VERSION 5.7 ;
  NOWIREEXTENSIONATPIN ON ;
  DIVIDERCHAR "/" ;
  BUSBITCHARS "[]" ;
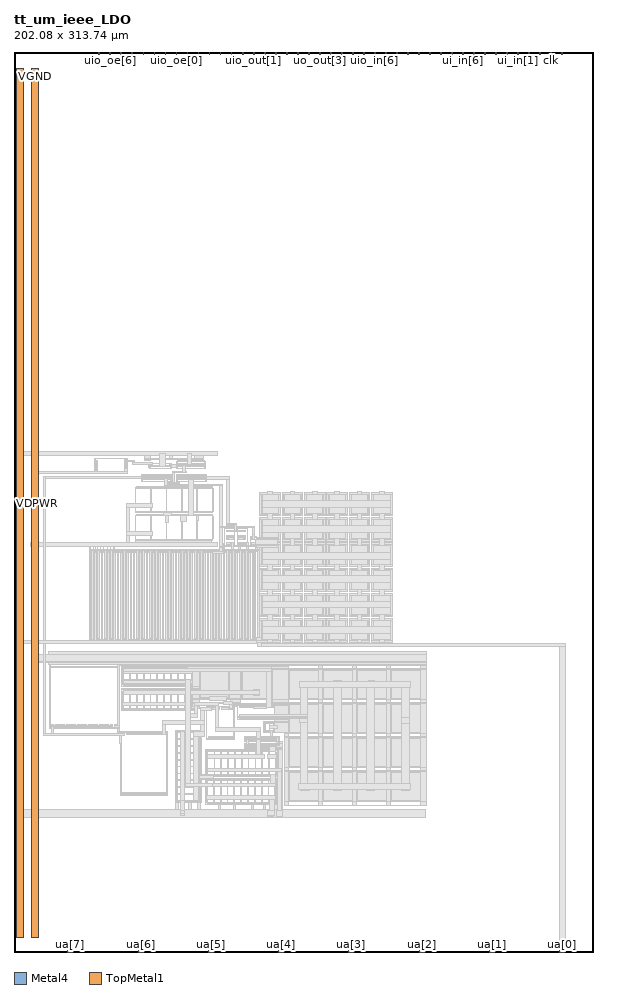
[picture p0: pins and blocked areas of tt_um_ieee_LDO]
MACRO tt_um_ieee_LDO
  CLASS BLOCK ;
  FOREIGN tt_um_ieee_LDO ;
  ORIGIN 0.000 0.000 ;
  SIZE 202.080 BY 313.740 ;
  PIN clk
    PORT
      LAYER Metal4 ;
        RECT 187.050 312.740 187.350 313.740 ;
    END
  END clk
  PIN ena
    PORT
      LAYER Metal4 ;
        RECT 190.890 312.740 191.190 313.740 ;
    END
  END ena
  PIN rst_n
    PORT
      LAYER Metal4 ;
        RECT 183.210 312.740 183.510 313.740 ;
    END
  END rst_n
  PIN ua[0]
    ANTENNADIFFAREA 559.200012 ;
    PORT
      LAYER TopMetal1 ;
        RECT 190.165 0.000 191.915 2.000 ;
    END
  END ua[0]
  PIN ua[1]
    PORT
      LAYER TopMetal1 ;
        RECT 165.685 0.000 167.435 2.000 ;
    END
  END ua[1]
  PIN ua[2]
    PORT
      LAYER TopMetal1 ;
        RECT 141.205 0.000 142.955 2.000 ;
    END
  END ua[2]
  PIN ua[3]
    PORT
      LAYER TopMetal1 ;
        RECT 116.725 0.000 118.475 2.000 ;
    END
  END ua[3]
  PIN ua[4]
    PORT
      LAYER TopMetal1 ;
        RECT 92.245 0.000 93.995 2.000 ;
    END
  END ua[4]
  PIN ua[5]
    PORT
      LAYER TopMetal1 ;
        RECT 67.765 0.000 69.515 2.000 ;
    END
  END ua[5]
  PIN ua[6]
    PORT
      LAYER TopMetal1 ;
        RECT 43.285 0.000 45.035 2.000 ;
    END
  END ua[6]
  PIN ua[7]
    PORT
      LAYER TopMetal1 ;
        RECT 18.805 0.000 20.555 2.000 ;
    END
  END ua[7]
  PIN ui_in[0]
    PORT
      LAYER Metal4 ;
        RECT 179.370 312.740 179.670 313.740 ;
    END
  END ui_in[0]
  PIN ui_in[1]
    PORT
      LAYER Metal4 ;
        RECT 175.530 312.740 175.830 313.740 ;
    END
  END ui_in[1]
  PIN ui_in[2]
    PORT
      LAYER Metal4 ;
        RECT 171.690 312.740 171.990 313.740 ;
    END
  END ui_in[2]
  PIN ui_in[3]
    PORT
      LAYER Metal4 ;
        RECT 167.850 312.740 168.150 313.740 ;
    END
  END ui_in[3]
  PIN ui_in[4]
    PORT
      LAYER Metal4 ;
        RECT 164.010 312.740 164.310 313.740 ;
    END
  END ui_in[4]
  PIN ui_in[5]
    PORT
      LAYER Metal4 ;
        RECT 160.170 312.740 160.470 313.740 ;
    END
  END ui_in[5]
  PIN ui_in[6]
    PORT
      LAYER Metal4 ;
        RECT 156.330 312.740 156.630 313.740 ;
    END
  END ui_in[6]
  PIN ui_in[7]
    PORT
      LAYER Metal4 ;
        RECT 152.490 312.740 152.790 313.740 ;
    END
  END ui_in[7]
  PIN uio_in[0]
    PORT
      LAYER Metal4 ;
        RECT 148.650 312.740 148.950 313.740 ;
    END
  END uio_in[0]
  PIN uio_in[1]
    PORT
      LAYER Metal4 ;
        RECT 144.810 312.740 145.110 313.740 ;
    END
  END uio_in[1]
  PIN uio_in[2]
    PORT
      LAYER Metal4 ;
        RECT 140.970 312.740 141.270 313.740 ;
    END
  END uio_in[2]
  PIN uio_in[3]
    PORT
      LAYER Metal4 ;
        RECT 137.130 312.740 137.430 313.740 ;
    END
  END uio_in[3]
  PIN uio_in[4]
    PORT
      LAYER Metal4 ;
        RECT 133.290 312.740 133.590 313.740 ;
    END
  END uio_in[4]
  PIN uio_in[5]
    PORT
      LAYER Metal4 ;
        RECT 129.450 312.740 129.750 313.740 ;
    END
  END uio_in[5]
  PIN uio_in[6]
    PORT
      LAYER Metal4 ;
        RECT 125.610 312.740 125.910 313.740 ;
    END
  END uio_in[6]
  PIN uio_in[7]
    PORT
      LAYER Metal4 ;
        RECT 121.770 312.740 122.070 313.740 ;
    END
  END uio_in[7]
  PIN uio_oe[0]
    PORT
      LAYER Metal4 ;
        RECT 56.490 312.740 56.790 313.740 ;
    END
  END uio_oe[0]
  PIN uio_oe[1]
    PORT
      LAYER Metal4 ;
        RECT 52.650 312.740 52.950 313.740 ;
    END
  END uio_oe[1]
  PIN uio_oe[2]
    PORT
      LAYER Metal4 ;
        RECT 48.810 312.740 49.110 313.740 ;
    END
  END uio_oe[2]
  PIN uio_oe[3]
    PORT
      LAYER Metal4 ;
        RECT 44.970 312.740 45.270 313.740 ;
    END
  END uio_oe[3]
  PIN uio_oe[4]
    PORT
      LAYER Metal4 ;
        RECT 41.130 312.740 41.430 313.740 ;
    END
  END uio_oe[4]
  PIN uio_oe[5]
    PORT
      LAYER Metal4 ;
        RECT 37.290 312.740 37.590 313.740 ;
    END
  END uio_oe[5]
  PIN uio_oe[6]
    PORT
      LAYER Metal4 ;
        RECT 33.450 312.740 33.750 313.740 ;
    END
  END uio_oe[6]
  PIN uio_oe[7]
    PORT
      LAYER Metal4 ;
        RECT 29.610 312.740 29.910 313.740 ;
    END
  END uio_oe[7]
  PIN uio_out[0]
    PORT
      LAYER Metal4 ;
        RECT 87.210 312.740 87.510 313.740 ;
    END
  END uio_out[0]
  PIN uio_out[1]
    PORT
      LAYER Metal4 ;
        RECT 83.370 312.740 83.670 313.740 ;
    END
  END uio_out[1]
  PIN uio_out[2]
    PORT
      LAYER Metal4 ;
        RECT 79.530 312.740 79.830 313.740 ;
    END
  END uio_out[2]
  PIN uio_out[3]
    PORT
      LAYER Metal4 ;
        RECT 75.690 312.740 75.990 313.740 ;
    END
  END uio_out[3]
  PIN uio_out[4]
    PORT
      LAYER Metal4 ;
        RECT 71.850 312.740 72.150 313.740 ;
    END
  END uio_out[4]
  PIN uio_out[5]
    PORT
      LAYER Metal4 ;
        RECT 68.010 312.740 68.310 313.740 ;
    END
  END uio_out[5]
  PIN uio_out[6]
    PORT
      LAYER Metal4 ;
        RECT 64.170 312.740 64.470 313.740 ;
    END
  END uio_out[6]
  PIN uio_out[7]
    PORT
      LAYER Metal4 ;
        RECT 60.330 312.740 60.630 313.740 ;
    END
  END uio_out[7]
  PIN uo_out[0]
    PORT
      LAYER Metal4 ;
        RECT 117.930 312.740 118.230 313.740 ;
    END
  END uo_out[0]
  PIN uo_out[1]
    PORT
      LAYER Metal4 ;
        RECT 114.090 312.740 114.390 313.740 ;
    END
  END uo_out[1]
  PIN uo_out[2]
    PORT
      LAYER Metal4 ;
        RECT 110.250 312.740 110.550 313.740 ;
    END
  END uo_out[2]
  PIN uo_out[3]
    PORT
      LAYER Metal4 ;
        RECT 106.410 312.740 106.710 313.740 ;
    END
  END uo_out[3]
  PIN uo_out[4]
    PORT
      LAYER Metal4 ;
        RECT 102.570 312.740 102.870 313.740 ;
    END
  END uo_out[4]
  PIN uo_out[5]
    PORT
      LAYER Metal4 ;
        RECT 98.730 312.740 99.030 313.740 ;
    END
  END uo_out[5]
  PIN uo_out[6]
    PORT
      LAYER Metal4 ;
        RECT 94.890 312.740 95.190 313.740 ;
    END
  END uo_out[6]
  PIN uo_out[7]
    PORT
      LAYER Metal4 ;
        RECT 91.050 312.740 91.350 313.740 ;
    END
  END uo_out[7]
  PIN VDPWR
    USE POWER ;
    PORT
      LAYER TopMetal1 ;
        RECT 1.000 5.000 3.400 308.000 ;
    END
  END VDPWR
  PIN VGND
    USE GROUND ;
    PORT
      LAYER TopMetal1 ;
        RECT 6.000 5.000 8.400 308.000 ;
    END
  END VGND
  OBS
      LAYER GatPoly ;
        RECT 28.760 170.900 29.190 171.400 ;
        RECT 38.390 170.900 38.820 171.400 ;
        RECT 56.500 170.430 56.870 170.910 ;
        RECT 66.540 170.430 66.910 170.910 ;
        RECT 28.760 169.920 29.190 170.420 ;
        RECT 38.390 169.920 38.820 170.420 ;
        RECT 47.060 169.630 47.430 170.110 ;
        RECT 54.680 169.630 55.050 170.110 ;
        RECT 56.500 169.570 56.870 170.050 ;
        RECT 66.540 169.570 66.910 170.050 ;
        RECT 28.760 168.940 29.190 169.440 ;
        RECT 38.390 168.940 38.820 169.440 ;
        RECT 47.060 168.770 47.430 169.250 ;
        RECT 54.680 168.770 55.050 169.250 ;
        RECT 56.500 168.710 56.870 169.190 ;
        RECT 66.540 168.710 66.910 169.190 ;
        RECT 28.760 167.960 29.190 168.460 ;
        RECT 38.390 167.960 38.820 168.460 ;
        RECT 44.290 165.770 44.660 166.170 ;
        RECT 54.660 165.770 55.030 166.170 ;
        RECT 56.500 165.730 56.870 166.130 ;
        RECT 66.870 165.730 67.240 166.130 ;
        RECT 44.290 164.990 44.660 165.390 ;
        RECT 54.660 164.990 55.030 165.390 ;
        RECT 56.500 164.950 56.870 165.350 ;
        RECT 66.870 164.950 67.240 165.350 ;
        RECT 44.290 164.210 44.660 164.610 ;
        RECT 54.660 164.210 55.030 164.610 ;
        RECT 56.500 164.170 56.870 164.570 ;
        RECT 66.870 164.170 67.240 164.570 ;
        RECT 42.570 161.740 47.570 162.110 ;
        RECT 47.950 161.740 52.950 162.110 ;
        RECT 53.330 161.740 58.330 162.110 ;
        RECT 58.710 161.740 63.710 162.110 ;
        RECT 64.090 161.740 69.090 162.110 ;
        RECT 42.570 153.270 47.570 153.640 ;
        RECT 47.950 153.270 52.950 153.640 ;
        RECT 53.330 153.270 58.330 153.640 ;
        RECT 58.710 153.270 63.710 153.640 ;
        RECT 64.090 153.270 69.090 153.640 ;
        RECT 42.570 152.020 47.570 152.390 ;
        RECT 47.950 152.020 52.950 152.390 ;
        RECT 53.330 152.020 58.330 152.390 ;
        RECT 58.710 152.020 63.710 152.390 ;
        RECT 64.090 152.020 69.090 152.390 ;
        RECT 73.930 146.595 74.430 147.025 ;
        RECT 74.910 146.595 75.410 147.025 ;
        RECT 75.890 146.595 76.390 147.025 ;
        RECT 78.390 146.575 78.890 147.005 ;
        RECT 79.370 146.575 79.870 147.005 ;
        RECT 80.350 146.575 80.850 147.005 ;
        RECT 73.930 144.865 74.430 145.295 ;
        RECT 74.910 144.865 75.410 145.295 ;
        RECT 75.890 144.865 76.390 145.295 ;
        RECT 78.390 144.845 78.890 145.275 ;
        RECT 79.370 144.845 79.870 145.275 ;
        RECT 80.350 144.845 80.850 145.275 ;
        RECT 42.570 143.550 47.570 143.920 ;
        RECT 47.950 143.550 52.950 143.920 ;
        RECT 53.330 143.550 58.330 143.920 ;
        RECT 58.710 143.550 63.710 143.920 ;
        RECT 64.090 143.550 69.090 143.920 ;
        RECT 73.930 143.915 74.430 144.345 ;
        RECT 74.910 143.915 75.410 144.345 ;
        RECT 75.890 143.915 76.390 144.345 ;
        RECT 78.390 143.895 78.890 144.325 ;
        RECT 79.370 143.895 79.870 144.325 ;
        RECT 80.350 143.895 80.850 144.325 ;
        RECT 82.930 143.625 83.930 144.055 ;
        RECT 73.930 142.185 74.430 142.615 ;
        RECT 74.910 142.185 75.410 142.615 ;
        RECT 75.890 142.185 76.390 142.615 ;
        RECT 78.390 142.165 78.890 142.595 ;
        RECT 79.370 142.165 79.870 142.595 ;
        RECT 80.350 142.165 80.850 142.595 ;
        RECT 82.930 142.195 83.930 142.625 ;
        RECT 27.670 139.095 28.070 139.465 ;
        RECT 28.790 139.095 29.190 139.465 ;
        RECT 29.910 139.095 30.310 139.465 ;
        RECT 31.030 139.095 31.430 139.465 ;
        RECT 32.150 139.095 32.550 139.465 ;
        RECT 33.270 139.095 33.670 139.465 ;
        RECT 34.390 139.095 34.790 139.465 ;
        RECT 35.510 139.095 35.910 139.465 ;
        RECT 36.630 139.095 37.030 139.465 ;
        RECT 37.750 139.095 38.150 139.465 ;
        RECT 38.870 139.095 39.270 139.465 ;
        RECT 39.990 139.095 40.390 139.465 ;
        RECT 41.110 139.095 41.510 139.465 ;
        RECT 42.230 139.095 42.630 139.465 ;
        RECT 43.350 139.095 43.750 139.465 ;
        RECT 44.470 139.095 44.870 139.465 ;
        RECT 45.590 139.095 45.990 139.465 ;
        RECT 46.710 139.095 47.110 139.465 ;
        RECT 47.830 139.095 48.230 139.465 ;
        RECT 48.950 139.095 49.350 139.465 ;
        RECT 50.070 139.095 50.470 139.465 ;
        RECT 51.190 139.095 51.590 139.465 ;
        RECT 52.310 139.095 52.710 139.465 ;
        RECT 53.430 139.095 53.830 139.465 ;
        RECT 54.550 139.095 54.950 139.465 ;
        RECT 55.670 139.095 56.070 139.465 ;
        RECT 56.790 139.095 57.190 139.465 ;
        RECT 57.910 139.095 58.310 139.465 ;
        RECT 59.030 139.095 59.430 139.465 ;
        RECT 60.150 139.095 60.550 139.465 ;
        RECT 61.270 139.095 61.670 139.465 ;
        RECT 62.390 139.095 62.790 139.465 ;
        RECT 63.510 139.095 63.910 139.465 ;
        RECT 64.630 139.095 65.030 139.465 ;
        RECT 65.750 139.095 66.150 139.465 ;
        RECT 66.870 139.095 67.270 139.465 ;
        RECT 67.990 139.095 68.390 139.465 ;
        RECT 69.110 139.095 69.510 139.465 ;
        RECT 70.230 139.095 70.630 139.465 ;
        RECT 71.350 139.095 71.750 139.465 ;
        RECT 72.470 139.095 72.870 139.465 ;
        RECT 73.590 139.095 73.990 139.465 ;
        RECT 74.710 139.095 75.110 139.465 ;
        RECT 75.830 139.095 76.230 139.465 ;
        RECT 76.950 139.095 77.350 139.465 ;
        RECT 78.070 139.095 78.470 139.465 ;
        RECT 79.190 139.095 79.590 139.465 ;
        RECT 80.310 139.095 80.710 139.465 ;
        RECT 81.430 139.095 81.830 139.465 ;
        RECT 82.550 139.095 82.950 139.465 ;
        RECT 27.670 108.725 28.070 109.095 ;
        RECT 28.790 108.725 29.190 109.095 ;
        RECT 29.910 108.725 30.310 109.095 ;
        RECT 31.030 108.725 31.430 109.095 ;
        RECT 32.150 108.725 32.550 109.095 ;
        RECT 33.270 108.725 33.670 109.095 ;
        RECT 34.390 108.725 34.790 109.095 ;
        RECT 35.510 108.725 35.910 109.095 ;
        RECT 36.630 108.725 37.030 109.095 ;
        RECT 37.750 108.725 38.150 109.095 ;
        RECT 38.870 108.725 39.270 109.095 ;
        RECT 39.990 108.725 40.390 109.095 ;
        RECT 41.110 108.725 41.510 109.095 ;
        RECT 42.230 108.725 42.630 109.095 ;
        RECT 43.350 108.725 43.750 109.095 ;
        RECT 44.470 108.725 44.870 109.095 ;
        RECT 45.590 108.725 45.990 109.095 ;
        RECT 46.710 108.725 47.110 109.095 ;
        RECT 47.830 108.725 48.230 109.095 ;
        RECT 48.950 108.725 49.350 109.095 ;
        RECT 50.070 108.725 50.470 109.095 ;
        RECT 51.190 108.725 51.590 109.095 ;
        RECT 52.310 108.725 52.710 109.095 ;
        RECT 53.430 108.725 53.830 109.095 ;
        RECT 54.550 108.725 54.950 109.095 ;
        RECT 55.670 108.725 56.070 109.095 ;
        RECT 56.790 108.725 57.190 109.095 ;
        RECT 57.910 108.725 58.310 109.095 ;
        RECT 59.030 108.725 59.430 109.095 ;
        RECT 60.150 108.725 60.550 109.095 ;
        RECT 61.270 108.725 61.670 109.095 ;
        RECT 62.390 108.725 62.790 109.095 ;
        RECT 63.510 108.725 63.910 109.095 ;
        RECT 64.630 108.725 65.030 109.095 ;
        RECT 65.750 108.725 66.150 109.095 ;
        RECT 66.870 108.725 67.270 109.095 ;
        RECT 67.990 108.725 68.390 109.095 ;
        RECT 69.110 108.725 69.510 109.095 ;
        RECT 70.230 108.725 70.630 109.095 ;
        RECT 71.350 108.725 71.750 109.095 ;
        RECT 72.470 108.725 72.870 109.095 ;
        RECT 73.590 108.725 73.990 109.095 ;
        RECT 74.710 108.725 75.110 109.095 ;
        RECT 75.830 108.725 76.230 109.095 ;
        RECT 76.950 108.725 77.350 109.095 ;
        RECT 78.070 108.725 78.470 109.095 ;
        RECT 79.190 108.725 79.590 109.095 ;
        RECT 80.310 108.725 80.710 109.095 ;
        RECT 81.430 108.725 81.830 109.095 ;
        RECT 82.550 108.725 82.950 109.095 ;
        RECT 13.100 99.140 13.900 99.570 ;
        RECT 14.380 99.140 15.180 99.570 ;
        RECT 15.660 99.140 16.460 99.570 ;
        RECT 16.940 99.140 17.740 99.570 ;
        RECT 18.220 99.140 19.020 99.570 ;
        RECT 19.500 99.140 20.300 99.570 ;
        RECT 20.780 99.140 21.580 99.570 ;
        RECT 22.060 99.140 22.860 99.570 ;
        RECT 23.340 99.140 24.140 99.570 ;
        RECT 24.620 99.140 25.420 99.570 ;
        RECT 25.900 99.140 26.700 99.570 ;
        RECT 27.180 99.140 27.980 99.570 ;
        RECT 28.460 99.140 29.260 99.570 ;
        RECT 29.740 99.140 30.540 99.570 ;
        RECT 31.020 99.140 31.820 99.570 ;
        RECT 32.300 99.140 33.100 99.570 ;
        RECT 33.580 99.140 34.380 99.570 ;
        RECT 34.860 99.140 35.660 99.570 ;
        RECT 38.260 99.140 40.260 99.510 ;
        RECT 40.640 99.140 42.640 99.510 ;
        RECT 43.020 99.140 45.020 99.510 ;
        RECT 45.400 99.140 47.400 99.510 ;
        RECT 47.780 99.140 49.780 99.510 ;
        RECT 50.160 99.140 52.160 99.510 ;
        RECT 52.540 99.140 54.540 99.510 ;
        RECT 54.920 99.140 56.920 99.510 ;
        RECT 57.300 99.140 59.300 99.510 ;
        RECT 59.680 99.140 61.680 99.510 ;
        RECT 38.260 92.770 40.260 93.140 ;
        RECT 40.640 92.770 42.640 93.140 ;
        RECT 43.020 92.770 45.020 93.140 ;
        RECT 45.400 92.770 47.400 93.140 ;
        RECT 47.780 92.770 49.780 93.140 ;
        RECT 50.160 92.770 52.160 93.140 ;
        RECT 52.540 92.770 54.540 93.140 ;
        RECT 54.920 92.770 56.920 93.140 ;
        RECT 57.300 92.770 59.300 93.140 ;
        RECT 59.680 92.770 61.680 93.140 ;
        RECT 38.260 91.020 40.260 91.390 ;
        RECT 40.640 91.020 42.640 91.390 ;
        RECT 43.020 91.020 45.020 91.390 ;
        RECT 45.400 91.020 47.400 91.390 ;
        RECT 47.780 91.020 49.780 91.390 ;
        RECT 50.160 91.020 52.160 91.390 ;
        RECT 52.540 91.020 54.540 91.390 ;
        RECT 54.920 91.020 56.920 91.390 ;
        RECT 57.300 91.020 59.300 91.390 ;
        RECT 59.680 91.020 61.680 91.390 ;
        RECT 38.260 84.650 40.260 85.020 ;
        RECT 40.640 84.650 42.640 85.020 ;
        RECT 43.020 84.650 45.020 85.020 ;
        RECT 45.400 84.650 47.400 85.020 ;
        RECT 47.780 84.650 49.780 85.020 ;
        RECT 50.160 84.650 52.160 85.020 ;
        RECT 52.540 84.650 54.540 85.020 ;
        RECT 54.920 84.650 56.920 85.020 ;
        RECT 57.300 84.650 59.300 85.020 ;
        RECT 59.680 84.650 61.680 85.020 ;
        RECT 67.740 84.670 68.740 85.100 ;
        RECT 69.220 84.670 70.220 85.100 ;
        RECT 70.700 84.670 71.700 85.100 ;
        RECT 72.180 84.670 73.180 85.100 ;
        RECT 73.660 84.670 74.660 85.100 ;
        RECT 75.140 84.670 76.140 85.100 ;
        RECT 78.480 85.070 80.480 85.500 ;
        RECT 80.960 85.070 82.960 85.500 ;
        RECT 83.440 85.070 85.440 85.500 ;
        RECT 85.920 85.070 87.920 85.500 ;
        RECT 88.400 85.070 90.400 85.500 ;
        RECT 78.480 81.640 80.480 82.070 ;
        RECT 80.960 81.640 82.960 82.070 ;
        RECT 83.440 81.640 85.440 82.070 ;
        RECT 85.920 81.640 87.920 82.070 ;
        RECT 88.400 81.640 90.400 82.070 ;
        RECT 87.880 79.550 88.880 79.920 ;
        RECT 89.260 79.550 90.260 79.920 ;
        RECT 13.100 78.710 13.900 79.140 ;
        RECT 14.380 78.710 15.180 79.140 ;
        RECT 15.660 78.710 16.460 79.140 ;
        RECT 16.940 78.710 17.740 79.140 ;
        RECT 18.220 78.710 19.020 79.140 ;
        RECT 19.500 78.710 20.300 79.140 ;
        RECT 20.780 78.710 21.580 79.140 ;
        RECT 22.060 78.710 22.860 79.140 ;
        RECT 23.340 78.710 24.140 79.140 ;
        RECT 24.620 78.710 25.420 79.140 ;
        RECT 25.900 78.710 26.700 79.140 ;
        RECT 27.180 78.710 27.980 79.140 ;
        RECT 28.460 78.710 29.260 79.140 ;
        RECT 29.740 78.710 30.540 79.140 ;
        RECT 31.020 78.710 31.820 79.140 ;
        RECT 32.300 78.710 33.100 79.140 ;
        RECT 33.580 78.710 34.380 79.140 ;
        RECT 34.860 78.710 35.660 79.140 ;
        RECT 87.880 76.680 88.880 77.050 ;
        RECT 89.260 76.680 90.260 77.050 ;
        RECT 37.850 75.680 38.650 76.110 ;
        RECT 39.130 75.680 39.930 76.110 ;
        RECT 40.410 75.680 41.210 76.110 ;
        RECT 41.690 75.680 42.490 76.110 ;
        RECT 42.970 75.680 43.770 76.110 ;
        RECT 44.250 75.680 45.050 76.110 ;
        RECT 45.530 75.680 46.330 76.110 ;
        RECT 46.810 75.680 47.610 76.110 ;
        RECT 48.090 75.680 48.890 76.110 ;
        RECT 49.370 75.680 50.170 76.110 ;
        RECT 50.650 75.680 51.450 76.110 ;
        RECT 51.930 75.680 52.730 76.110 ;
        RECT 56.610 74.350 56.980 76.350 ;
        RECT 64.780 74.350 65.150 76.350 ;
        RECT 67.740 74.740 68.740 75.170 ;
        RECT 69.220 74.740 70.220 75.170 ;
        RECT 70.700 74.740 71.700 75.170 ;
        RECT 72.180 74.740 73.180 75.170 ;
        RECT 73.660 74.740 74.660 75.170 ;
        RECT 75.140 74.740 76.140 75.170 ;
        RECT 81.050 74.430 91.050 74.800 ;
        RECT 56.610 71.970 56.980 73.970 ;
        RECT 64.780 71.970 65.150 73.970 ;
        RECT 81.050 73.560 91.050 73.930 ;
        RECT 81.050 72.160 91.050 72.530 ;
        RECT 56.610 69.590 56.980 71.590 ;
        RECT 64.780 69.590 65.150 71.590 ;
        RECT 81.050 71.290 91.050 71.660 ;
        RECT 67.680 69.770 69.680 70.140 ;
        RECT 70.060 69.770 72.060 70.140 ;
        RECT 72.440 69.770 74.440 70.140 ;
        RECT 74.820 69.770 76.820 70.140 ;
        RECT 77.200 69.770 79.200 70.140 ;
        RECT 79.580 69.770 81.580 70.140 ;
        RECT 81.960 69.770 83.960 70.140 ;
        RECT 84.340 69.770 86.340 70.140 ;
        RECT 86.720 69.770 88.720 70.140 ;
        RECT 89.100 69.770 91.100 70.140 ;
        RECT 56.610 67.210 56.980 69.210 ;
        RECT 64.780 67.210 65.150 69.210 ;
        RECT 56.610 64.830 56.980 66.830 ;
        RECT 64.780 64.830 65.150 66.830 ;
        RECT 56.610 62.450 56.980 64.450 ;
        RECT 64.780 62.450 65.150 64.450 ;
        RECT 56.610 60.070 56.980 62.070 ;
        RECT 64.780 60.070 65.150 62.070 ;
        RECT 67.680 61.600 69.680 61.970 ;
        RECT 70.060 61.600 72.060 61.970 ;
        RECT 72.440 61.600 74.440 61.970 ;
        RECT 74.820 61.600 76.820 61.970 ;
        RECT 77.200 61.600 79.200 61.970 ;
        RECT 79.580 61.600 81.580 61.970 ;
        RECT 81.960 61.600 83.960 61.970 ;
        RECT 84.340 61.600 86.340 61.970 ;
        RECT 86.720 61.600 88.720 61.970 ;
        RECT 89.100 61.600 91.100 61.970 ;
        RECT 67.480 59.790 69.480 60.160 ;
        RECT 69.860 59.790 71.860 60.160 ;
        RECT 72.240 59.790 74.240 60.160 ;
        RECT 74.620 59.790 76.620 60.160 ;
        RECT 77.000 59.790 79.000 60.160 ;
        RECT 79.380 59.790 81.380 60.160 ;
        RECT 81.760 59.790 83.760 60.160 ;
        RECT 84.140 59.790 86.140 60.160 ;
        RECT 86.520 59.790 88.520 60.160 ;
        RECT 88.900 59.790 90.900 60.160 ;
        RECT 56.610 57.690 56.980 59.690 ;
        RECT 64.780 57.690 65.150 59.690 ;
        RECT 37.850 55.250 38.650 55.680 ;
        RECT 39.130 55.250 39.930 55.680 ;
        RECT 40.410 55.250 41.210 55.680 ;
        RECT 41.690 55.250 42.490 55.680 ;
        RECT 42.970 55.250 43.770 55.680 ;
        RECT 44.250 55.250 45.050 55.680 ;
        RECT 45.530 55.250 46.330 55.680 ;
        RECT 46.810 55.250 47.610 55.680 ;
        RECT 48.090 55.250 48.890 55.680 ;
        RECT 49.370 55.250 50.170 55.680 ;
        RECT 50.650 55.250 51.450 55.680 ;
        RECT 51.930 55.250 52.730 55.680 ;
        RECT 56.610 55.310 56.980 57.310 ;
        RECT 64.780 55.310 65.150 57.310 ;
        RECT 56.610 52.930 56.980 54.930 ;
        RECT 64.780 52.930 65.150 54.930 ;
        RECT 67.480 51.620 69.480 51.990 ;
        RECT 69.860 51.620 71.860 51.990 ;
        RECT 72.240 51.620 74.240 51.990 ;
        RECT 74.620 51.620 76.620 51.990 ;
        RECT 77.000 51.620 79.000 51.990 ;
        RECT 79.380 51.620 81.380 51.990 ;
        RECT 81.760 51.620 83.760 51.990 ;
        RECT 84.140 51.620 86.140 51.990 ;
        RECT 86.520 51.620 88.520 51.990 ;
        RECT 88.900 51.620 90.900 51.990 ;
      LAYER Metal1 ;
        RECT 1.840 174.530 2.540 174.700 ;
        RECT 1.190 173.250 70.810 174.530 ;
        RECT 45.320 172.140 47.720 173.250 ;
        RECT 50.980 173.130 51.680 173.250 ;
        RECT 54.070 172.140 55.380 173.250 ;
        RECT 60.710 173.030 61.410 173.250 ;
        RECT 62.780 172.140 66.210 173.250 ;
        RECT 28.120 171.880 39.460 172.040 ;
        RECT 28.120 167.660 28.280 171.880 ;
        RECT 28.740 169.860 29.100 171.450 ;
        RECT 38.520 170.840 38.900 171.520 ;
        RECT 28.710 167.890 29.070 169.480 ;
        RECT 38.470 168.850 38.870 170.490 ;
        RECT 39.300 168.470 39.460 171.880 ;
        RECT 45.320 171.650 66.210 172.140 ;
        RECT 45.320 171.510 47.720 171.650 ;
        RECT 62.780 171.500 66.210 171.650 ;
        RECT 47.750 170.430 48.450 170.680 ;
        RECT 47.500 170.300 54.890 170.430 ;
        RECT 47.130 168.580 47.290 170.300 ;
        RECT 47.500 170.170 54.980 170.300 ;
        RECT 47.750 170.060 48.450 170.170 ;
        RECT 54.070 169.980 54.980 170.170 ;
        RECT 54.820 169.960 54.980 169.980 ;
        RECT 56.570 169.960 56.730 171.100 ;
        RECT 56.940 170.970 66.470 171.230 ;
        RECT 60.750 170.370 61.450 170.720 ;
        RECT 56.940 170.110 66.470 170.370 ;
        RECT 60.750 170.100 61.450 170.110 ;
        RECT 51.340 169.570 52.040 169.880 ;
        RECT 47.500 169.310 54.610 169.570 ;
        RECT 51.340 169.260 52.040 169.310 ;
        RECT 54.820 169.060 56.730 169.960 ;
        RECT 58.740 169.510 59.440 169.520 ;
        RECT 56.940 169.250 66.470 169.510 ;
        RECT 38.440 167.660 39.460 168.470 ;
        RECT 47.500 168.450 54.610 168.710 ;
        RECT 54.820 168.580 54.980 169.060 ;
        RECT 56.570 168.520 56.730 169.060 ;
        RECT 58.740 168.900 59.440 169.250 ;
        RECT 56.940 168.390 66.470 168.650 ;
        RECT 66.680 168.520 66.840 171.100 ;
        RECT 6.540 166.910 39.460 167.660 ;
        RECT 55.400 167.395 56.100 167.640 ;
        RECT 58.920 167.395 59.620 167.970 ;
        RECT 55.400 167.150 60.260 167.395 ;
        RECT 44.360 165.770 44.520 166.360 ;
        RECT 44.730 166.230 54.590 166.490 ;
        RECT 10.320 165.030 44.520 165.770 ;
        RECT 44.730 165.450 54.590 165.710 ;
        RECT 44.360 164.020 44.520 165.030 ;
        RECT 44.730 164.670 54.590 164.930 ;
        RECT 53.990 164.150 54.590 164.170 ;
        RECT 44.730 163.890 54.590 164.150 ;
        RECT 54.800 164.020 54.960 166.360 ;
        RECT 53.990 163.760 54.590 163.890 ;
        RECT 53.990 163.755 54.630 163.760 ;
        RECT 55.400 163.755 56.100 167.150 ;
        RECT 56.570 163.980 56.730 166.320 ;
        RECT 56.940 166.190 66.800 166.450 ;
        RECT 56.940 165.410 66.800 165.670 ;
        RECT 67.010 165.660 67.170 166.320 ;
        RECT 61.150 164.890 61.850 165.090 ;
        RECT 56.940 164.630 66.800 164.890 ;
        RECT 67.010 164.870 74.965 165.660 ;
        RECT 61.150 164.470 61.850 164.630 ;
        RECT 56.940 164.110 57.610 164.130 ;
        RECT 56.940 163.850 66.800 164.110 ;
        RECT 67.010 163.980 67.170 164.870 ;
        RECT 56.940 163.755 57.610 163.850 ;
        RECT 52.770 162.890 53.470 163.360 ;
        RECT 53.990 163.350 57.610 163.755 ;
        RECT 55.400 163.200 56.100 163.350 ;
        RECT 52.360 162.530 72.720 162.890 ;
        RECT 42.380 161.880 69.280 162.040 ;
        RECT 40.160 155.920 40.340 155.930 ;
        RECT 39.220 155.720 40.340 155.920 ;
        RECT 39.190 155.100 40.340 155.720 ;
        RECT 39.220 154.960 40.340 155.100 ;
        RECT 39.220 146.380 40.380 154.960 ;
        RECT 42.250 153.710 42.510 161.670 ;
        RECT 47.630 156.030 47.890 161.670 ;
        RECT 47.410 155.410 48.110 156.030 ;
        RECT 47.630 153.710 47.890 155.410 ;
        RECT 53.010 153.710 53.270 161.670 ;
        RECT 58.390 153.710 58.650 161.670 ;
        RECT 63.770 153.710 64.030 161.670 ;
        RECT 69.150 153.710 69.410 161.670 ;
        RECT 42.380 153.340 69.280 153.500 ;
        RECT 52.180 152.320 55.020 153.340 ;
        RECT 61.560 152.320 62.260 152.770 ;
        RECT 42.380 152.160 69.280 152.320 ;
        RECT 52.180 152.150 55.020 152.160 ;
        RECT 39.220 145.920 40.340 146.380 ;
        RECT 39.190 145.300 40.340 145.920 ;
        RECT 39.220 145.280 40.340 145.300 ;
        RECT 39.220 142.760 40.380 145.280 ;
        RECT 42.250 143.990 42.510 151.950 ;
        RECT 47.630 146.360 47.890 151.950 ;
        RECT 52.960 149.810 54.030 152.150 ;
        RECT 58.160 150.150 60.220 152.160 ;
        RECT 61.560 152.150 62.260 152.160 ;
        RECT 63.770 150.330 64.390 152.160 ;
        RECT 47.340 145.740 48.040 146.360 ;
        RECT 47.630 143.990 47.890 145.740 ;
        RECT 53.010 143.990 53.270 149.810 ;
        RECT 58.390 143.990 58.650 150.150 ;
        RECT 63.770 143.990 64.030 150.330 ;
        RECT 69.150 143.990 69.410 151.950 ;
        RECT 71.800 148.280 72.720 162.530 ;
        RECT 74.175 149.440 74.965 164.870 ;
        RECT 74.175 149.160 77.720 149.440 ;
        RECT 74.170 149.090 77.720 149.160 ;
        RECT 74.170 148.660 77.730 149.090 ;
        RECT 77.030 148.470 77.730 148.660 ;
        RECT 71.800 147.920 83.790 148.280 ;
        RECT 42.380 143.620 69.280 143.780 ;
        RECT 25.020 142.750 40.380 142.760 ;
        RECT 5.885 142.740 41.060 142.750 ;
        RECT 42.470 142.740 68.980 143.380 ;
        RECT 5.885 141.460 70.810 142.740 ;
        RECT 5.885 141.400 41.060 141.460 ;
        RECT 26.270 139.765 26.430 141.400 ;
        RECT 26.670 139.765 26.830 141.400 ;
        RECT 27.690 139.765 27.850 141.400 ;
        RECT 28.370 139.765 28.530 141.400 ;
        RECT 29.050 139.765 29.210 141.400 ;
        RECT 30.070 139.765 30.230 141.400 ;
        RECT 31.090 139.765 31.250 141.400 ;
        RECT 32.450 139.765 32.610 141.400 ;
        RECT 33.470 139.765 33.630 141.400 ;
        RECT 34.830 139.765 34.990 141.400 ;
        RECT 39.830 141.380 41.060 141.400 ;
        RECT 71.800 140.510 72.720 147.920 ;
        RECT 73.290 147.505 77.030 147.665 ;
        RECT 73.290 142.575 73.450 147.505 ;
        RECT 73.950 146.705 74.440 147.065 ;
        RECT 73.950 146.690 74.410 146.705 ;
        RECT 74.930 146.675 75.420 147.035 ;
        RECT 75.910 146.665 76.400 147.025 ;
        RECT 73.950 144.875 74.440 145.235 ;
        RECT 74.930 144.845 75.420 145.205 ;
        RECT 75.910 145.195 76.370 145.200 ;
        RECT 75.910 144.835 76.400 145.195 ;
        RECT 73.950 144.005 74.440 144.365 ;
        RECT 74.910 143.995 75.430 144.355 ;
        RECT 75.890 143.995 76.410 144.355 ;
        RECT 72.970 141.825 73.540 142.575 ;
        RECT 73.950 142.175 74.440 142.555 ;
        RECT 74.920 142.195 75.410 142.555 ;
        RECT 75.900 142.195 76.390 142.555 ;
        RECT 76.870 141.825 77.030 147.505 ;
        RECT 77.750 147.485 81.490 147.645 ;
        RECT 77.750 141.825 77.910 147.485 ;
        RECT 78.410 146.670 78.870 147.005 ;
        RECT 79.390 146.670 79.850 147.005 ;
        RECT 80.370 146.670 80.830 147.005 ;
        RECT 78.390 144.865 78.880 145.225 ;
        RECT 79.390 144.855 79.880 145.215 ;
        RECT 80.370 144.855 80.860 145.215 ;
        RECT 78.410 143.995 78.900 144.355 ;
        RECT 79.390 143.995 79.880 144.355 ;
        RECT 78.410 143.990 78.870 143.995 ;
        RECT 79.390 143.990 79.850 143.995 ;
        RECT 80.370 143.985 80.860 144.345 ;
        RECT 81.330 142.595 81.490 147.485 ;
        RECT 83.100 145.600 83.790 147.920 ;
        RECT 83.100 144.980 83.800 145.600 ;
        RECT 83.100 144.940 83.790 144.980 ;
        RECT 82.290 144.535 84.570 144.695 ;
        RECT 78.340 141.825 78.910 142.585 ;
        RECT 79.380 142.155 79.870 142.515 ;
        RECT 80.360 142.165 80.850 142.525 ;
        RECT 81.130 141.825 81.700 142.595 ;
        RECT 82.290 141.825 82.450 144.535 ;
        RECT 82.950 143.715 83.910 144.105 ;
        RECT 84.410 142.535 84.570 144.535 ;
        RECT 82.950 142.185 83.910 142.530 ;
        RECT 84.190 141.825 84.760 142.535 ;
        RECT 72.970 141.385 84.760 141.825 ;
        RECT 72.970 139.765 73.540 141.385 ;
        RECT 78.340 139.765 78.910 141.385 ;
        RECT 81.130 139.765 81.700 141.385 ;
        RECT 84.190 139.765 84.760 141.385 ;
        RECT 26.270 139.605 84.760 139.765 ;
        RECT 26.270 108.585 26.430 139.605 ;
        RECT 26.670 139.600 26.830 139.605 ;
        RECT 28.370 139.600 28.530 139.605 ;
        RECT 72.970 139.595 73.540 139.605 ;
        RECT 84.190 139.555 84.760 139.605 ;
        RECT 26.630 139.235 83.990 139.395 ;
        RECT 26.630 108.955 26.790 139.235 ;
        RECT 27.010 109.165 27.610 139.025 ;
        RECT 28.130 109.165 28.730 139.025 ;
        RECT 29.250 109.165 29.850 139.025 ;
        RECT 30.370 109.165 30.970 139.025 ;
        RECT 31.490 109.165 32.090 139.025 ;
        RECT 32.610 109.165 33.210 139.025 ;
        RECT 33.730 109.165 34.330 139.025 ;
        RECT 34.850 109.165 35.450 139.025 ;
        RECT 35.970 109.165 36.570 139.025 ;
        RECT 37.090 109.165 37.690 139.025 ;
        RECT 38.210 109.165 38.810 139.025 ;
        RECT 39.330 109.165 39.930 139.025 ;
        RECT 40.450 109.165 41.050 139.025 ;
        RECT 41.570 109.165 42.170 139.025 ;
        RECT 42.690 109.165 43.290 139.025 ;
        RECT 43.810 109.165 44.410 139.025 ;
        RECT 44.930 109.165 45.530 139.025 ;
        RECT 46.050 109.165 46.650 139.025 ;
        RECT 47.170 109.165 47.770 139.025 ;
        RECT 48.290 109.165 48.890 139.025 ;
        RECT 49.410 109.165 50.010 139.025 ;
        RECT 50.530 109.165 51.130 139.025 ;
        RECT 51.650 109.165 52.250 139.025 ;
        RECT 52.770 109.165 53.370 139.025 ;
        RECT 53.890 109.165 54.490 139.025 ;
        RECT 55.010 109.165 55.610 139.025 ;
        RECT 56.130 109.165 56.730 139.025 ;
        RECT 57.250 109.165 57.850 139.025 ;
        RECT 58.370 109.165 58.970 139.025 ;
        RECT 59.490 109.165 60.090 139.025 ;
        RECT 60.610 109.165 61.210 139.025 ;
        RECT 61.730 109.165 62.330 139.025 ;
        RECT 62.850 109.165 63.450 139.025 ;
        RECT 63.970 109.165 64.570 139.025 ;
        RECT 65.090 109.165 65.690 139.025 ;
        RECT 66.210 109.165 66.810 139.025 ;
        RECT 67.330 109.165 67.930 139.025 ;
        RECT 68.450 109.165 69.050 139.025 ;
        RECT 69.570 109.165 70.170 139.025 ;
        RECT 70.690 109.165 71.290 139.025 ;
        RECT 71.810 109.165 72.410 139.025 ;
        RECT 72.930 109.165 73.530 139.025 ;
        RECT 74.050 109.165 74.650 139.025 ;
        RECT 75.170 109.165 75.770 139.025 ;
        RECT 76.290 109.165 76.890 139.025 ;
        RECT 77.410 109.165 78.010 139.025 ;
        RECT 78.530 109.165 79.130 139.025 ;
        RECT 79.650 109.165 80.250 139.025 ;
        RECT 80.770 109.165 81.370 139.025 ;
        RECT 81.890 109.165 82.490 139.025 ;
        RECT 83.010 109.165 83.610 139.025 ;
        RECT 83.830 108.955 83.990 139.235 ;
        RECT 26.630 108.795 83.990 108.955 ;
        RECT 84.190 108.585 84.350 139.555 ;
        RECT 26.270 108.425 84.350 108.585 ;
        RECT 84.970 106.590 192.190 107.580 ;
        RECT 12.090 104.820 37.150 104.830 ;
        RECT 12.090 104.810 143.520 104.820 ;
        RECT 12.090 103.710 143.760 104.810 ;
        RECT 6.170 101.220 143.760 103.710 ;
        RECT 6.170 101.080 143.770 101.220 ;
        RECT 12.090 100.050 143.770 101.080 ;
        RECT 12.460 78.230 12.620 100.050 ;
        RECT 13.050 99.200 15.260 99.580 ;
        RECT 15.590 99.220 17.800 99.600 ;
        RECT 18.140 99.250 20.350 99.630 ;
        RECT 20.690 99.230 22.900 99.610 ;
        RECT 23.290 99.170 25.500 99.610 ;
        RECT 25.820 99.190 28.030 99.570 ;
        RECT 28.370 99.180 30.580 99.560 ;
        RECT 30.920 99.200 33.130 99.580 ;
        RECT 33.490 99.220 35.700 99.600 ;
        RECT 12.910 78.650 14.020 79.050 ;
        RECT 14.310 78.630 16.520 79.010 ;
        RECT 16.850 78.620 19.060 79.000 ;
        RECT 19.450 78.640 21.660 79.020 ;
        RECT 22.010 78.630 24.220 79.010 ;
        RECT 24.550 78.640 26.760 79.020 ;
        RECT 27.080 78.650 29.290 79.030 ;
        RECT 29.630 78.640 31.840 79.020 ;
        RECT 32.200 78.660 34.410 79.040 ;
        RECT 36.130 79.030 36.750 100.050 ;
        RECT 37.060 100.030 143.770 100.050 ;
        RECT 62.300 99.950 143.770 100.030 ;
        RECT 62.300 99.810 95.720 99.950 ;
        RECT 37.480 99.650 95.720 99.810 ;
        RECT 37.480 92.630 37.640 99.650 ;
        RECT 38.070 99.280 61.870 99.440 ;
        RECT 37.940 94.690 38.200 99.070 ;
        RECT 40.320 98.460 40.580 99.070 ;
        RECT 40.320 97.430 40.640 98.460 ;
        RECT 37.940 93.660 38.290 94.690 ;
        RECT 37.940 93.210 38.200 93.660 ;
        RECT 40.320 93.210 40.580 97.430 ;
        RECT 42.700 94.720 42.960 99.070 ;
        RECT 42.670 93.690 42.960 94.720 ;
        RECT 42.700 93.210 42.960 93.690 ;
        RECT 45.080 98.510 45.340 99.070 ;
        RECT 45.080 97.480 45.410 98.510 ;
        RECT 45.080 93.210 45.340 97.480 ;
        RECT 47.460 94.780 47.720 99.070 ;
        RECT 49.840 98.530 50.100 99.070 ;
        RECT 49.840 97.500 50.190 98.530 ;
        RECT 47.460 93.750 47.770 94.780 ;
        RECT 47.460 93.210 47.720 93.750 ;
        RECT 49.840 93.210 50.100 97.500 ;
        RECT 52.220 94.720 52.480 99.070 ;
        RECT 54.600 98.460 54.860 99.070 ;
        RECT 54.600 97.430 54.920 98.460 ;
        RECT 52.220 93.690 52.560 94.720 ;
        RECT 52.220 93.210 52.480 93.690 ;
        RECT 54.600 93.210 54.860 97.430 ;
        RECT 56.980 94.710 57.240 99.070 ;
        RECT 59.360 98.610 59.620 99.070 ;
        RECT 59.360 97.580 59.700 98.610 ;
        RECT 56.980 93.680 57.320 94.710 ;
        RECT 56.980 93.210 57.240 93.680 ;
        RECT 59.360 93.210 59.620 97.580 ;
        RECT 61.740 94.760 62.000 99.070 ;
        RECT 62.300 98.800 95.720 99.650 ;
        RECT 106.290 98.800 107.580 99.950 ;
        RECT 118.140 98.800 119.430 99.950 ;
        RECT 130.010 98.800 131.260 99.950 ;
        RECT 141.850 98.800 143.770 99.950 ;
        RECT 62.300 98.760 143.770 98.800 ;
        RECT 61.740 93.730 62.030 94.760 ;
        RECT 61.740 93.210 62.000 93.730 ;
        RECT 59.810 93.000 61.540 93.030 ;
        RECT 38.070 92.840 61.870 93.000 ;
        RECT 59.810 92.820 61.540 92.840 ;
        RECT 62.300 92.630 64.670 98.760 ;
        RECT 37.480 92.470 64.670 92.630 ;
        RECT 62.300 91.690 64.670 92.470 ;
        RECT 37.480 91.530 64.670 91.690 ;
        RECT 37.480 84.510 37.640 91.530 ;
        RECT 38.070 91.160 61.870 91.320 ;
        RECT 59.800 91.060 61.530 91.160 ;
        RECT 37.940 86.540 38.200 90.950 ;
        RECT 40.320 90.510 40.580 90.950 ;
        RECT 40.290 89.480 40.580 90.510 ;
        RECT 37.940 85.510 38.250 86.540 ;
        RECT 37.940 84.880 38.200 85.510 ;
        RECT 40.320 85.090 40.580 89.480 ;
        RECT 42.700 86.460 42.960 90.950 ;
        RECT 45.080 90.440 45.340 90.950 ;
        RECT 45.030 89.410 45.340 90.440 ;
        RECT 42.700 85.430 42.990 86.460 ;
        RECT 42.700 84.880 42.960 85.430 ;
        RECT 45.080 85.090 45.340 89.410 ;
        RECT 47.460 86.500 47.720 90.950 ;
        RECT 49.840 90.510 50.100 90.950 ;
        RECT 49.770 89.480 50.100 90.510 ;
        RECT 47.420 85.470 47.720 86.500 ;
        RECT 47.460 84.880 47.720 85.470 ;
        RECT 49.840 85.090 50.100 89.480 ;
        RECT 52.220 86.530 52.480 90.950 ;
        RECT 54.600 90.510 54.860 90.950 ;
        RECT 54.570 89.480 54.860 90.510 ;
        RECT 52.220 85.500 52.560 86.530 ;
        RECT 52.220 84.880 52.480 85.500 ;
        RECT 54.600 85.090 54.860 89.480 ;
        RECT 56.980 86.460 57.240 90.950 ;
        RECT 59.360 90.590 59.620 90.950 ;
        RECT 59.310 89.560 59.620 90.590 ;
        RECT 56.920 85.430 57.240 86.460 ;
        RECT 56.980 84.880 57.240 85.430 ;
        RECT 59.360 85.090 59.620 89.560 ;
        RECT 61.740 86.520 62.000 90.950 ;
        RECT 61.710 85.670 62.000 86.520 ;
        RECT 62.300 88.200 64.670 91.530 ;
        RECT 64.970 88.550 74.930 98.410 ;
        RECT 75.230 88.200 79.110 98.760 ;
        RECT 62.300 88.040 79.110 88.200 ;
        RECT 62.300 86.890 64.670 88.040 ;
        RECT 75.360 86.890 79.110 88.040 ;
        RECT 79.350 98.670 143.770 98.760 ;
        RECT 79.350 88.110 79.510 98.670 ;
        RECT 90.070 98.640 143.770 98.670 ;
        RECT 79.810 88.460 89.770 98.320 ;
        RECT 90.070 88.110 95.730 98.640 ;
        RECT 96.030 88.430 105.990 98.290 ;
        RECT 79.350 88.080 95.730 88.110 ;
        RECT 106.290 88.080 107.580 98.640 ;
        RECT 107.880 88.430 117.840 98.290 ;
        RECT 118.140 88.080 119.430 98.640 ;
        RECT 119.730 88.430 129.690 98.290 ;
        RECT 129.990 88.080 131.280 98.640 ;
        RECT 131.580 88.430 141.540 98.290 ;
        RECT 141.840 88.080 143.770 98.640 ;
        RECT 79.350 87.950 143.770 88.080 ;
        RECT 62.300 86.800 79.110 86.890 ;
        RECT 90.070 87.920 143.770 87.950 ;
        RECT 90.070 86.950 95.720 87.920 ;
        RECT 106.290 86.950 107.580 87.920 ;
        RECT 118.140 86.950 119.430 87.920 ;
        RECT 130.010 86.950 131.260 87.920 ;
        RECT 141.850 86.950 143.770 87.920 ;
        RECT 90.070 86.800 143.770 86.950 ;
        RECT 62.300 86.790 143.770 86.800 ;
        RECT 62.300 86.680 95.730 86.790 ;
        RECT 62.300 85.670 64.670 86.680 ;
        RECT 76.350 86.590 95.730 86.680 ;
        RECT 76.350 86.140 77.980 86.590 ;
        RECT 90.070 86.140 95.730 86.590 ;
        RECT 76.350 85.980 95.730 86.140 ;
        RECT 76.350 85.740 78.000 85.980 ;
        RECT 61.710 85.490 64.670 85.670 ;
        RECT 60.270 84.880 61.380 84.920 ;
        RECT 61.740 84.880 64.670 85.490 ;
        RECT 37.940 84.750 64.670 84.880 ;
        RECT 67.100 85.580 78.000 85.740 ;
        RECT 37.940 84.720 62.460 84.750 ;
        RECT 37.940 84.700 38.200 84.720 ;
        RECT 60.270 84.710 61.380 84.720 ;
        RECT 62.300 84.510 62.460 84.720 ;
        RECT 37.480 84.350 62.460 84.510 ;
        RECT 34.870 78.340 36.750 79.030 ;
        RECT 34.870 78.230 36.770 78.340 ;
        RECT 12.460 78.070 36.770 78.230 ;
        RECT 36.150 76.730 36.770 78.070 ;
        RECT 56.310 76.970 65.450 77.130 ;
        RECT 37.210 76.730 53.370 76.750 ;
        RECT 36.150 76.590 53.370 76.730 ;
        RECT 36.150 75.730 37.540 76.590 ;
        RECT 37.810 75.800 38.670 76.140 ;
        RECT 36.830 72.640 37.530 75.730 ;
        RECT 39.080 75.690 41.300 76.180 ;
        RECT 41.690 75.690 43.910 76.180 ;
        RECT 44.200 75.690 46.420 76.180 ;
        RECT 46.740 75.700 48.960 76.190 ;
        RECT 49.290 75.700 51.510 76.190 ;
        RECT 51.890 75.730 52.760 76.140 ;
        RECT 37.210 54.770 37.370 72.640 ;
        RECT 37.860 55.230 40.020 55.590 ;
        RECT 40.380 55.230 42.540 55.590 ;
        RECT 42.940 55.220 45.100 55.580 ;
        RECT 45.500 55.210 47.660 55.570 ;
        RECT 48.040 55.210 50.200 55.570 ;
        RECT 50.630 55.210 52.790 55.570 ;
        RECT 53.210 54.770 53.370 76.590 ;
        RECT 37.210 54.610 53.370 54.770 ;
        RECT 56.310 52.310 56.470 76.970 ;
        RECT 56.680 52.740 56.840 76.540 ;
        RECT 57.050 76.410 64.710 76.670 ;
        RECT 58.020 74.290 59.130 74.320 ;
        RECT 57.050 74.030 64.710 74.290 ;
        RECT 63.110 71.910 64.220 71.920 ;
        RECT 57.050 71.650 64.710 71.910 ;
        RECT 57.050 69.270 64.710 69.530 ;
        RECT 57.050 66.890 64.710 67.150 ;
        RECT 57.050 64.510 64.710 64.770 ;
        RECT 57.050 62.130 64.710 62.390 ;
        RECT 64.920 61.570 65.080 76.540 ;
        RECT 64.830 60.460 65.080 61.570 ;
        RECT 58.090 60.010 59.200 60.050 ;
        RECT 57.050 59.750 64.710 60.010 ;
        RECT 57.050 57.370 64.710 57.630 ;
        RECT 58.140 55.250 59.250 55.290 ;
        RECT 57.050 54.990 64.710 55.250 ;
        RECT 63.060 52.870 64.170 52.880 ;
        RECT 57.050 52.610 64.710 52.870 ;
        RECT 64.920 52.740 65.080 60.460 ;
        RECT 65.290 52.310 65.450 76.970 ;
        RECT 67.100 74.260 67.260 85.580 ;
        RECT 76.350 85.570 78.000 85.580 ;
        RECT 67.580 84.660 68.800 85.140 ;
        RECT 69.220 84.630 71.770 85.100 ;
        RECT 72.200 84.630 74.750 85.100 ;
        RECT 75.060 84.690 76.290 85.150 ;
        RECT 72.050 75.110 73.270 75.120 ;
        RECT 69.070 75.090 70.290 75.100 ;
        RECT 67.640 74.620 70.290 75.090 ;
        RECT 70.600 74.640 73.270 75.110 ;
        RECT 73.610 74.690 76.160 75.160 ;
        RECT 76.620 74.260 76.780 85.570 ;
        RECT 77.840 81.160 78.000 85.570 ;
        RECT 78.470 85.080 82.970 85.510 ;
        RECT 83.410 85.050 87.910 85.480 ;
        RECT 88.350 85.120 90.470 85.560 ;
        RECT 78.350 81.600 80.560 81.980 ;
        RECT 80.930 81.550 85.430 81.980 ;
        RECT 85.900 81.600 90.400 82.120 ;
        RECT 90.880 81.160 95.730 85.980 ;
        RECT 77.840 81.000 95.730 81.160 ;
        RECT 90.880 80.220 95.730 81.000 ;
        RECT 87.100 80.060 95.730 80.220 ;
        RECT 87.100 76.540 87.260 80.060 ;
        RECT 87.690 79.690 90.450 79.850 ;
        RECT 87.560 76.910 87.820 79.480 ;
        RECT 88.940 78.960 89.200 79.480 ;
        RECT 88.930 77.930 89.220 78.960 ;
        RECT 88.940 77.120 89.200 77.930 ;
        RECT 89.430 76.910 90.130 76.950 ;
        RECT 90.320 76.910 90.580 79.480 ;
        RECT 87.560 76.750 90.580 76.910 ;
        RECT 89.430 76.740 90.130 76.750 ;
        RECT 90.880 76.580 95.730 80.060 ;
        RECT 96.030 76.580 105.990 86.440 ;
        RECT 90.880 76.540 91.040 76.580 ;
        RECT 91.650 76.570 95.730 76.580 ;
        RECT 87.100 76.380 91.040 76.540 ;
        RECT 94.200 76.230 95.730 76.570 ;
        RECT 106.290 76.230 107.580 86.790 ;
        RECT 107.880 76.580 117.840 86.440 ;
        RECT 118.140 76.230 119.430 86.790 ;
        RECT 119.730 76.580 129.690 86.440 ;
        RECT 129.990 76.230 131.280 86.790 ;
        RECT 131.580 76.580 141.540 86.440 ;
        RECT 141.840 76.230 143.770 86.790 ;
        RECT 94.200 76.070 143.770 76.230 ;
        RECT 91.620 75.100 92.050 75.190 ;
        RECT 67.100 74.100 76.780 74.260 ;
        RECT 80.270 74.940 92.050 75.100 ;
        RECT 80.270 73.420 80.430 74.940 ;
        RECT 89.640 74.730 89.930 74.740 ;
        RECT 80.860 74.570 91.240 74.730 ;
        RECT 89.640 74.530 89.930 74.570 ;
        RECT 80.730 74.320 80.990 74.360 ;
        RECT 91.110 74.330 91.370 74.360 ;
        RECT 80.700 74.110 80.990 74.320 ;
        RECT 91.070 74.120 91.370 74.330 ;
        RECT 80.730 74.000 80.990 74.110 ;
        RECT 91.110 74.000 91.370 74.120 ;
        RECT 80.860 73.630 91.240 73.790 ;
        RECT 91.620 73.420 92.050 74.940 ;
        RECT 80.270 73.290 92.050 73.420 ;
        RECT 94.200 75.100 95.730 76.070 ;
        RECT 106.290 75.100 107.580 76.070 ;
        RECT 118.140 75.100 119.430 76.070 ;
        RECT 130.010 75.100 131.260 76.070 ;
        RECT 141.850 75.100 143.770 76.070 ;
        RECT 94.200 74.940 143.770 75.100 ;
        RECT 80.270 73.280 92.840 73.290 ;
        RECT 80.270 73.260 93.520 73.280 ;
        RECT 91.620 72.830 93.520 73.260 ;
        RECT 80.270 72.670 93.520 72.830 ;
        RECT 80.270 72.090 80.430 72.670 ;
        RECT 81.130 72.460 81.830 72.470 ;
        RECT 80.860 72.300 91.240 72.460 ;
        RECT 81.130 72.260 81.830 72.300 ;
        RECT 80.270 71.730 80.990 72.090 ;
        RECT 91.110 71.730 91.370 72.090 ;
        RECT 80.270 71.150 80.430 71.730 ;
        RECT 89.570 71.520 90.680 71.570 ;
        RECT 80.860 71.360 91.240 71.520 ;
        RECT 91.620 71.150 93.520 72.670 ;
        RECT 80.270 70.990 93.520 71.150 ;
        RECT 91.620 70.730 93.520 70.990 ;
        RECT 66.900 70.280 91.880 70.440 ;
        RECT 66.900 61.460 67.060 70.280 ;
        RECT 67.490 69.910 91.290 70.070 ;
        RECT 89.510 69.830 90.620 69.910 ;
        RECT 67.360 68.600 67.620 69.700 ;
        RECT 67.360 67.570 67.690 68.600 ;
        RECT 67.360 62.040 67.620 67.570 ;
        RECT 69.740 64.070 70.000 69.700 ;
        RECT 72.120 68.700 72.380 69.700 ;
        RECT 72.110 67.670 72.400 68.700 ;
        RECT 69.740 63.040 70.080 64.070 ;
        RECT 69.740 62.040 70.000 63.040 ;
        RECT 72.120 62.040 72.380 67.670 ;
        RECT 74.500 64.020 74.760 69.700 ;
        RECT 76.880 68.650 77.140 69.700 ;
        RECT 76.880 67.620 77.210 68.650 ;
        RECT 74.500 62.990 74.790 64.020 ;
        RECT 74.500 62.040 74.760 62.990 ;
        RECT 76.880 62.040 77.140 67.620 ;
        RECT 79.260 64.070 79.520 69.700 ;
        RECT 79.210 63.040 79.520 64.070 ;
        RECT 79.260 62.040 79.520 63.040 ;
        RECT 81.640 68.650 81.900 69.700 ;
        RECT 81.640 67.620 81.940 68.650 ;
        RECT 81.640 62.040 81.900 67.620 ;
        RECT 84.020 64.020 84.280 69.700 ;
        RECT 86.400 68.600 86.660 69.700 ;
        RECT 86.360 67.570 86.660 68.600 ;
        RECT 84.020 62.990 84.330 64.020 ;
        RECT 84.020 62.040 84.280 62.990 ;
        RECT 86.400 62.040 86.660 67.570 ;
        RECT 88.780 64.070 89.040 69.700 ;
        RECT 91.160 68.730 91.420 69.700 ;
        RECT 91.160 67.700 91.450 68.730 ;
        RECT 88.780 63.040 89.110 64.070 ;
        RECT 88.780 62.040 89.040 63.040 ;
        RECT 91.160 62.040 91.420 67.700 ;
        RECT 68.120 61.830 69.230 61.850 ;
        RECT 89.620 61.830 90.730 61.860 ;
        RECT 67.490 61.670 91.290 61.830 ;
        RECT 68.120 61.640 69.230 61.670 ;
        RECT 89.620 61.650 90.730 61.670 ;
        RECT 91.720 61.460 91.880 70.280 ;
        RECT 66.900 61.300 91.880 61.460 ;
        RECT 56.310 52.250 65.450 52.310 ;
        RECT 56.270 52.150 65.450 52.250 ;
        RECT 66.700 60.300 91.680 60.460 ;
        RECT 56.270 49.770 57.280 52.150 ;
        RECT 60.870 49.770 61.880 52.150 ;
        RECT 63.840 49.770 64.850 52.150 ;
        RECT 66.700 51.480 66.860 60.300 ;
        RECT 67.290 59.930 91.090 60.090 ;
        RECT 67.880 59.870 68.990 59.930 ;
        RECT 89.430 59.880 90.540 59.930 ;
        RECT 67.160 58.770 67.420 59.720 ;
        RECT 67.160 57.740 67.450 58.770 ;
        RECT 68.400 58.240 69.100 58.860 ;
        RECT 67.160 52.060 67.420 57.740 ;
        RECT 69.540 54.410 69.800 59.720 ;
        RECT 71.920 58.820 72.180 59.720 ;
        RECT 71.920 57.790 72.290 58.820 ;
        RECT 69.540 53.380 69.850 54.410 ;
        RECT 69.540 52.060 69.800 53.380 ;
        RECT 71.920 52.060 72.180 57.790 ;
        RECT 74.300 54.340 74.560 59.720 ;
        RECT 76.680 58.790 76.940 59.720 ;
        RECT 76.680 57.760 76.990 58.790 ;
        RECT 74.300 53.310 74.600 54.340 ;
        RECT 74.300 52.060 74.560 53.310 ;
        RECT 76.680 52.060 76.940 57.760 ;
        RECT 79.060 54.360 79.320 59.720 ;
        RECT 81.440 58.790 81.700 59.720 ;
        RECT 81.430 57.760 81.720 58.790 ;
        RECT 79.010 53.330 79.320 54.360 ;
        RECT 79.060 52.060 79.320 53.330 ;
        RECT 81.440 52.060 81.700 57.760 ;
        RECT 83.820 54.430 84.080 59.720 ;
        RECT 86.200 58.890 86.460 59.720 ;
        RECT 86.200 57.860 86.510 58.890 ;
        RECT 83.800 53.400 84.090 54.430 ;
        RECT 83.820 52.060 84.080 53.400 ;
        RECT 86.200 52.060 86.460 57.860 ;
        RECT 88.580 54.340 88.840 59.720 ;
        RECT 90.960 58.770 91.220 59.720 ;
        RECT 90.960 57.740 91.290 58.770 ;
        RECT 88.570 53.310 88.860 54.340 ;
        RECT 88.580 52.060 88.840 53.310 ;
        RECT 90.960 52.060 91.220 57.740 ;
        RECT 67.290 51.690 91.090 51.850 ;
        RECT 91.520 51.480 91.680 60.300 ;
        RECT 66.700 51.470 91.680 51.480 ;
        RECT 66.700 51.320 91.690 51.470 ;
        RECT 71.130 49.770 71.880 51.320 ;
        RECT 76.600 49.770 77.350 51.320 ;
        RECT 82.770 49.770 83.520 51.320 ;
        RECT 86.960 49.770 87.710 51.320 ;
        RECT 90.940 49.770 91.690 51.320 ;
        RECT 92.130 49.770 93.520 70.730 ;
        RECT 94.200 64.380 95.730 74.940 ;
        RECT 96.030 64.730 105.990 74.590 ;
        RECT 106.290 64.380 107.580 74.940 ;
        RECT 107.880 64.730 117.840 74.590 ;
        RECT 118.140 64.380 119.430 74.940 ;
        RECT 119.730 64.730 129.690 74.590 ;
        RECT 129.990 64.380 131.280 74.940 ;
        RECT 131.580 64.730 141.540 74.590 ;
        RECT 141.840 64.380 143.770 74.940 ;
        RECT 94.200 64.220 143.770 64.380 ;
        RECT 94.200 63.250 95.730 64.220 ;
        RECT 106.290 63.250 107.580 64.220 ;
        RECT 118.140 63.250 119.430 64.220 ;
        RECT 130.010 63.250 131.260 64.220 ;
        RECT 141.850 63.250 143.770 64.220 ;
        RECT 94.200 63.090 143.770 63.250 ;
        RECT 94.200 52.530 95.730 63.090 ;
        RECT 96.030 52.880 105.990 62.740 ;
        RECT 106.290 52.530 107.580 63.090 ;
        RECT 107.880 52.880 117.840 62.740 ;
        RECT 118.140 52.530 119.430 63.090 ;
        RECT 119.730 52.880 129.690 62.740 ;
        RECT 129.990 52.530 131.280 63.090 ;
        RECT 131.580 52.880 141.540 62.740 ;
        RECT 141.840 52.530 143.770 63.090 ;
        RECT 94.200 52.370 143.770 52.530 ;
        RECT 94.200 51.220 95.730 52.370 ;
        RECT 106.290 51.220 107.580 52.370 ;
        RECT 118.140 51.220 119.430 52.370 ;
        RECT 130.010 51.220 131.260 52.370 ;
        RECT 141.850 51.220 143.770 52.370 ;
        RECT 94.200 51.010 143.770 51.220 ;
        RECT 14.560 49.750 143.420 49.770 ;
        RECT 1.010 46.950 143.420 49.750 ;
        RECT 1.010 46.930 129.870 46.950 ;
        RECT 190.130 0.050 192.190 106.590 ;
      LAYER Metal2 ;
        RECT 1.885 174.040 2.495 174.740 ;
        RECT 51.025 173.750 51.635 173.790 ;
        RECT 38.580 170.940 41.960 171.470 ;
        RECT 41.200 170.590 41.960 170.940 ;
        RECT 47.795 170.590 48.405 170.720 ;
        RECT 41.200 169.930 48.450 170.590 ;
        RECT 50.670 169.270 52.770 173.750 ;
        RECT 60.500 170.000 61.860 173.920 ;
        RECT 58.785 169.490 59.395 169.560 ;
        RECT 51.385 169.220 51.995 169.270 ;
        RECT 58.630 167.150 59.700 169.490 ;
        RECT 7.035 141.850 7.645 142.550 ;
        RECT 10.320 108.470 11.120 165.740 ;
        RECT 52.610 162.640 53.440 164.980 ;
        RECT 61.195 164.580 61.805 165.130 ;
        RECT 39.190 156.280 40.820 156.310 ;
        RECT 39.190 155.060 48.250 156.280 ;
        RECT 40.340 154.960 48.250 155.060 ;
        RECT 60.860 152.100 62.570 164.580 ;
        RECT 77.075 149.085 77.685 149.130 ;
        RECT 73.930 146.615 75.390 147.045 ;
        RECT 75.960 146.995 76.320 147.020 ;
        RECT 77.000 146.995 77.730 149.085 ;
        RECT 78.460 146.995 78.820 147.000 ;
        RECT 75.950 146.685 78.840 146.995 ;
        RECT 75.960 146.650 76.320 146.685 ;
        RECT 78.460 146.630 78.820 146.685 ;
        RECT 40.340 146.540 48.250 146.600 ;
        RECT 79.330 146.595 80.790 147.025 ;
        RECT 39.190 145.280 48.250 146.540 ;
        RECT 83.145 145.385 83.755 145.640 ;
        RECT 39.190 145.260 40.510 145.280 ;
        RECT 74.000 145.225 74.360 145.240 ;
        RECT 73.950 143.965 74.370 145.225 ;
        RECT 74.930 144.845 76.390 145.275 ;
        RECT 78.430 144.845 79.890 145.275 ;
        RECT 74.930 143.935 76.390 144.365 ;
        RECT 78.420 143.935 79.880 144.365 ;
        RECT 80.390 144.005 80.810 145.265 ;
        RECT 80.420 143.950 80.780 144.005 ;
        RECT 83.000 143.680 83.860 145.385 ;
        RECT 84.860 143.105 85.500 144.525 ;
        RECT 84.860 142.705 88.230 143.105 ;
        RECT 73.970 142.175 75.430 142.605 ;
        RECT 71.965 140.690 72.575 141.390 ;
        RECT 75.820 140.455 76.400 142.615 ;
        RECT 78.390 142.165 78.860 142.565 ;
        RECT 79.390 142.145 80.850 142.575 ;
        RECT 82.840 142.075 88.230 142.705 ;
        RECT 82.840 142.065 85.500 142.075 ;
        RECT 26.710 139.945 85.565 140.455 ;
        RECT 27.010 109.065 27.640 139.945 ;
        RECT 28.090 108.470 28.720 139.395 ;
        RECT 29.250 109.155 29.880 139.945 ;
        RECT 30.350 108.470 30.980 139.395 ;
        RECT 31.490 109.155 32.120 139.945 ;
        RECT 32.570 108.470 33.200 139.395 ;
        RECT 33.730 109.155 34.360 139.945 ;
        RECT 34.820 108.470 35.450 139.385 ;
        RECT 35.970 109.135 36.600 139.945 ;
        RECT 37.070 108.470 37.700 139.385 ;
        RECT 38.210 109.145 38.840 139.945 ;
        RECT 39.300 108.470 39.930 139.365 ;
        RECT 40.470 109.155 41.100 139.945 ;
        RECT 41.540 108.470 42.170 139.405 ;
        RECT 42.700 109.155 43.330 139.945 ;
        RECT 43.770 108.470 44.400 139.395 ;
        RECT 44.930 109.155 45.560 139.945 ;
        RECT 46.020 108.470 46.650 139.355 ;
        RECT 47.170 109.155 47.800 139.945 ;
        RECT 48.290 108.470 48.920 139.375 ;
        RECT 49.420 109.165 50.050 139.945 ;
        RECT 50.520 108.470 51.150 139.375 ;
        RECT 51.630 109.155 52.260 139.945 ;
        RECT 52.750 108.470 53.380 139.355 ;
        RECT 53.890 109.175 54.520 139.945 ;
        RECT 54.980 108.470 55.610 139.375 ;
        RECT 56.130 109.135 56.760 139.945 ;
        RECT 57.260 108.470 57.890 139.375 ;
        RECT 58.370 109.145 59.000 139.945 ;
        RECT 59.470 108.470 60.100 139.385 ;
        RECT 60.620 109.145 61.250 139.945 ;
        RECT 61.680 108.470 62.310 139.365 ;
        RECT 62.870 109.135 63.500 139.945 ;
        RECT 63.940 108.470 64.570 139.395 ;
        RECT 65.110 109.145 65.740 139.945 ;
        RECT 66.160 108.470 66.790 139.375 ;
        RECT 67.310 109.135 67.940 139.945 ;
        RECT 68.430 108.470 69.060 139.325 ;
        RECT 69.570 109.145 70.200 139.945 ;
        RECT 70.680 108.470 71.310 139.355 ;
        RECT 71.790 109.145 72.420 139.945 ;
        RECT 72.920 108.470 73.550 139.395 ;
        RECT 74.070 109.135 74.700 139.945 ;
        RECT 75.140 108.470 75.770 139.425 ;
        RECT 76.270 109.145 76.900 139.945 ;
        RECT 77.380 108.470 78.010 139.395 ;
        RECT 78.530 109.135 79.160 139.945 ;
        RECT 79.630 108.470 80.260 139.405 ;
        RECT 80.760 109.145 81.390 139.945 ;
        RECT 81.890 108.470 82.520 139.355 ;
        RECT 83.010 109.155 83.640 139.945 ;
        RECT 84.975 109.755 85.485 139.945 ;
        RECT 2.070 108.455 25.030 108.470 ;
        RECT 26.290 108.455 84.390 108.470 ;
        RECT 2.070 107.640 84.390 108.455 ;
        RECT 84.690 108.005 86.170 109.755 ;
        RECT 6.855 101.760 7.465 102.460 ;
        RECT 10.320 76.140 11.120 107.640 ;
        RECT 84.970 106.590 86.170 108.005 ;
        RECT 60.345 98.740 89.860 99.505 ;
        RECT 38.190 97.715 89.860 98.740 ;
        RECT 38.190 97.210 62.240 97.715 ;
        RECT 38.240 94.730 62.290 94.950 ;
        RECT 38.045 93.620 62.290 94.730 ;
        RECT 38.240 93.420 62.290 93.620 ;
        RECT 59.855 92.990 61.495 93.070 ;
        RECT 59.855 92.780 61.860 92.990 ;
        RECT 59.980 91.560 61.860 92.780 ;
        RECT 83.425 91.310 85.545 91.630 ;
        RECT 59.845 91.160 61.485 91.310 ;
        RECT 83.420 91.160 85.750 91.310 ;
        RECT 38.190 89.780 85.750 91.160 ;
        RECT 40.335 89.440 40.535 89.780 ;
        RECT 45.075 89.370 45.275 89.780 ;
        RECT 49.815 89.440 50.015 89.780 ;
        RECT 54.615 89.440 54.815 89.780 ;
        RECT 59.355 89.520 59.555 89.780 ;
        RECT 83.425 89.420 85.545 89.780 ;
        RECT 68.320 87.810 74.250 89.240 ;
        RECT 72.900 87.280 74.250 87.810 ;
        RECT 37.990 85.910 62.040 87.010 ;
        RECT 38.005 85.470 38.205 85.910 ;
        RECT 42.745 85.390 42.945 85.910 ;
        RECT 47.465 85.430 47.665 85.910 ;
        RECT 52.315 85.460 52.515 85.910 ;
        RECT 56.965 85.390 57.165 85.910 ;
        RECT 61.755 85.450 61.955 85.910 ;
        RECT 62.820 85.850 71.390 87.130 ;
        RECT 72.900 86.420 76.160 87.280 ;
        RECT 72.910 86.170 76.160 86.420 ;
        RECT 60.200 83.120 61.480 85.260 ;
        RECT 62.820 83.120 64.100 85.850 ;
        RECT 60.200 81.840 64.100 83.120 ;
        RECT 65.110 84.290 68.690 85.310 ;
        RECT 51.790 80.680 52.980 80.690 ;
        RECT 65.110 80.680 66.540 84.290 ;
        RECT 51.790 79.180 66.540 80.680 ;
        RECT 12.955 78.690 13.975 78.980 ;
        RECT 13.140 76.140 13.880 78.690 ;
        RECT 10.320 75.340 38.630 76.140 ;
        RECT 51.790 75.680 52.980 79.180 ;
        RECT 65.110 76.710 66.540 79.180 ;
        RECT 70.110 78.160 71.390 85.850 ;
        RECT 75.120 84.730 76.160 86.170 ;
        RECT 88.070 85.150 89.860 97.715 ;
        RECT 99.760 94.450 102.410 94.470 ;
        RECT 111.470 94.450 114.120 94.540 ;
        RECT 123.595 94.450 125.715 94.560 ;
        RECT 99.650 92.220 138.260 94.450 ;
        RECT 99.760 82.850 102.410 92.220 ;
        RECT 78.460 81.940 102.410 82.850 ;
        RECT 78.395 81.650 102.410 81.940 ;
        RECT 78.460 81.370 102.410 81.650 ;
        RECT 99.685 79.900 102.410 81.370 ;
        RECT 70.110 76.880 85.830 78.160 ;
        RECT 88.970 78.040 91.920 79.000 ;
        RECT 88.975 77.890 89.175 78.040 ;
        RECT 91.675 77.890 91.875 78.040 ;
        RECT 57.930 52.690 59.570 76.700 ;
        RECT 57.940 49.360 59.570 52.690 ;
        RECT 62.700 75.210 66.540 76.710 ;
        RECT 62.700 52.680 64.340 75.210 ;
        RECT 80.720 73.960 81.850 74.410 ;
        RECT 84.550 74.270 85.830 76.880 ;
        RECT 89.400 75.240 90.190 77.100 ;
        RECT 89.400 74.630 92.590 75.240 ;
        RECT 89.400 74.590 90.190 74.630 ;
        RECT 89.685 74.490 89.885 74.590 ;
        RECT 91.115 74.270 91.315 74.370 ;
        RECT 81.040 72.310 81.840 73.960 ;
        RECT 84.550 73.930 91.360 74.270 ;
        RECT 81.175 72.220 81.785 72.310 ;
        RECT 84.550 68.750 85.830 73.930 ;
        RECT 92.070 72.330 92.590 74.630 ;
        RECT 91.130 71.900 92.590 72.330 ;
        RECT 92.070 71.880 92.590 71.900 ;
        RECT 89.170 69.910 91.110 71.610 ;
        RECT 89.555 69.790 90.575 69.910 ;
        RECT 91.205 68.750 91.405 68.770 ;
        RECT 67.400 67.610 87.350 68.750 ;
        RECT 88.410 67.610 91.420 68.750 ;
        RECT 67.445 67.530 67.645 67.610 ;
        RECT 76.965 67.580 77.165 67.610 ;
        RECT 81.695 67.580 81.895 67.610 ;
        RECT 86.405 67.530 86.605 67.610 ;
        RECT 90.460 64.110 93.420 64.130 ;
        RECT 67.410 62.970 93.420 64.110 ;
        RECT 74.545 62.950 74.745 62.970 ;
        RECT 84.085 62.950 84.285 62.970 ;
        RECT 90.460 62.950 93.420 62.970 ;
        RECT 68.165 61.840 69.185 61.890 ;
        RECT 64.800 61.525 69.450 61.840 ;
        RECT 89.665 61.830 90.685 61.900 ;
        RECT 64.790 60.505 69.450 61.525 ;
        RECT 64.800 60.180 69.450 60.505 ;
        RECT 67.540 59.840 69.450 60.180 ;
        RECT 67.925 59.830 68.945 59.840 ;
        RECT 68.445 58.860 69.055 58.900 ;
        RECT 86.265 58.860 86.465 58.930 ;
        RECT 89.260 58.860 91.030 61.830 ;
        RECT 67.200 58.810 91.220 58.860 ;
        RECT 67.200 57.720 91.245 58.810 ;
        RECT 67.205 57.700 67.405 57.720 ;
        RECT 91.045 57.700 91.245 57.720 ;
        RECT 69.605 54.420 69.805 54.450 ;
        RECT 83.845 54.420 84.045 54.470 ;
        RECT 67.270 53.280 91.290 54.420 ;
        RECT 74.355 53.270 74.555 53.280 ;
        RECT 88.615 53.270 88.815 53.280 ;
        RECT 63.105 52.630 64.125 52.680 ;
        RECT 89.090 49.360 90.660 53.280 ;
        RECT 1.755 47.630 2.365 48.330 ;
        RECT 57.885 48.260 59.570 49.360 ;
        RECT 57.885 47.630 59.525 48.260 ;
        RECT 88.415 47.500 90.660 49.360 ;
        RECT 91.970 49.310 93.420 62.950 ;
        RECT 99.760 58.830 102.410 79.900 ;
        RECT 111.470 58.830 114.120 92.220 ;
        RECT 123.020 58.830 125.670 92.220 ;
        RECT 135.190 81.850 137.840 92.220 ;
        RECT 135.105 79.640 137.840 81.850 ;
        RECT 135.190 58.840 137.840 79.640 ;
        RECT 135.190 58.830 138.065 58.840 ;
        RECT 99.220 56.630 138.065 58.830 ;
        RECT 99.220 56.600 137.840 56.630 ;
        RECT 99.760 56.380 103.065 56.600 ;
        RECT 111.470 56.420 114.120 56.600 ;
        RECT 111.845 56.380 113.965 56.420 ;
        RECT 99.760 56.350 102.410 56.380 ;
        RECT 123.020 56.280 125.670 56.600 ;
        RECT 135.190 56.310 137.840 56.600 ;
        RECT 123.265 56.250 125.385 56.280 ;
        RECT 88.415 47.150 90.535 47.500 ;
        RECT 91.555 47.100 93.675 49.310 ;
        RECT 190.785 1.860 191.395 2.560 ;
      LAYER Metal3 ;
        RECT 1.840 174.085 2.540 174.695 ;
        RECT 84.790 142.705 85.510 142.905 ;
        RECT 6.990 141.895 7.690 142.505 ;
        RECT 71.920 141.080 72.620 141.345 ;
        RECT 71.690 139.450 72.850 141.080 ;
        RECT 69.220 139.050 72.870 139.450 ;
        RECT 71.690 139.040 72.850 139.050 ;
        RECT 2.090 108.140 2.810 108.340 ;
        RECT 84.770 108.230 85.470 108.840 ;
        RECT 6.810 101.805 7.510 102.415 ;
        RECT 59.890 58.900 61.580 94.870 ;
        RECT 59.870 57.690 69.100 58.900 ;
        RECT 1.710 47.675 2.410 48.285 ;
        RECT 190.740 1.905 191.440 2.515 ;
      LAYER Metal4 ;
        RECT 1.885 174.040 2.495 174.740 ;
        RECT 7.035 141.850 7.645 142.550 ;
        RECT 85.050 142.445 85.250 143.165 ;
        RECT 2.350 107.880 2.550 108.600 ;
        RECT 84.815 108.185 85.425 108.885 ;
        RECT 6.855 101.760 7.465 102.460 ;
        RECT 1.755 47.630 2.365 48.330 ;
        RECT 190.785 1.860 191.395 2.560 ;
      LAYER Metal5 ;
        RECT 1.460 173.660 2.920 175.120 ;
        RECT 88.790 160.225 89.790 160.525 ;
        RECT 96.590 160.225 97.590 160.525 ;
        RECT 104.390 160.225 105.390 160.525 ;
        RECT 112.190 160.225 113.190 160.525 ;
        RECT 119.990 160.225 120.990 160.525 ;
        RECT 127.790 160.225 128.790 160.525 ;
        RECT 85.690 159.625 92.890 160.225 ;
        RECT 85.690 152.625 86.290 159.625 ;
        RECT 92.290 152.625 92.890 159.625 ;
        RECT 85.690 152.025 92.890 152.625 ;
        RECT 93.490 159.625 100.690 160.225 ;
        RECT 93.490 152.625 94.090 159.625 ;
        RECT 100.090 152.625 100.690 159.625 ;
        RECT 93.490 152.025 100.690 152.625 ;
        RECT 101.290 159.625 108.490 160.225 ;
        RECT 101.290 152.625 101.890 159.625 ;
        RECT 107.890 152.625 108.490 159.625 ;
        RECT 101.290 152.025 108.490 152.625 ;
        RECT 109.090 159.625 116.290 160.225 ;
        RECT 109.090 152.625 109.690 159.625 ;
        RECT 115.690 152.625 116.290 159.625 ;
        RECT 109.090 152.025 116.290 152.625 ;
        RECT 116.890 159.625 124.090 160.225 ;
        RECT 116.890 152.625 117.490 159.625 ;
        RECT 123.490 152.625 124.090 159.625 ;
        RECT 116.890 152.025 124.090 152.625 ;
        RECT 124.690 159.625 131.890 160.225 ;
        RECT 124.690 152.625 125.290 159.625 ;
        RECT 131.290 152.625 131.890 159.625 ;
        RECT 124.690 152.025 131.890 152.625 ;
        RECT 88.790 151.425 89.790 152.025 ;
        RECT 96.590 151.425 97.590 152.025 ;
        RECT 104.390 151.425 105.390 152.025 ;
        RECT 112.190 151.425 113.190 152.025 ;
        RECT 119.990 151.425 120.990 152.025 ;
        RECT 127.790 151.425 128.790 152.025 ;
        RECT 85.690 150.825 92.890 151.425 ;
        RECT 85.690 143.825 86.290 150.825 ;
        RECT 92.290 143.825 92.890 150.825 ;
        RECT 85.690 143.225 92.890 143.825 ;
        RECT 93.490 150.825 100.690 151.425 ;
        RECT 93.490 143.825 94.090 150.825 ;
        RECT 100.090 143.825 100.690 150.825 ;
        RECT 93.490 143.225 100.690 143.825 ;
        RECT 101.290 150.825 108.490 151.425 ;
        RECT 101.290 143.825 101.890 150.825 ;
        RECT 107.890 143.825 108.490 150.825 ;
        RECT 101.290 143.225 108.490 143.825 ;
        RECT 109.090 150.825 116.290 151.425 ;
        RECT 109.090 143.825 109.690 150.825 ;
        RECT 115.690 143.825 116.290 150.825 ;
        RECT 109.090 143.225 116.290 143.825 ;
        RECT 116.890 150.825 124.090 151.425 ;
        RECT 116.890 143.825 117.490 150.825 ;
        RECT 123.490 143.825 124.090 150.825 ;
        RECT 116.890 143.225 124.090 143.825 ;
        RECT 124.690 150.825 131.890 151.425 ;
        RECT 124.690 143.825 125.290 150.825 ;
        RECT 131.290 143.825 131.890 150.825 ;
        RECT 124.690 143.225 131.890 143.825 ;
        RECT 6.610 141.470 8.070 142.930 ;
        RECT 84.840 142.495 85.460 143.115 ;
        RECT 88.790 142.625 89.790 143.225 ;
        RECT 96.590 142.625 97.590 143.225 ;
        RECT 104.390 142.625 105.390 143.225 ;
        RECT 112.190 142.625 113.190 143.225 ;
        RECT 119.990 142.625 120.990 143.225 ;
        RECT 127.790 142.625 128.790 143.225 ;
        RECT 85.690 142.025 92.890 142.625 ;
        RECT 85.690 135.025 86.290 142.025 ;
        RECT 92.290 135.025 92.890 142.025 ;
        RECT 85.690 134.425 92.890 135.025 ;
        RECT 93.490 142.025 100.690 142.625 ;
        RECT 93.490 135.025 94.090 142.025 ;
        RECT 100.090 135.025 100.690 142.025 ;
        RECT 93.490 134.425 100.690 135.025 ;
        RECT 101.290 142.025 108.490 142.625 ;
        RECT 101.290 135.025 101.890 142.025 ;
        RECT 107.890 135.025 108.490 142.025 ;
        RECT 101.290 134.425 108.490 135.025 ;
        RECT 109.090 142.025 116.290 142.625 ;
        RECT 109.090 135.025 109.690 142.025 ;
        RECT 115.690 135.025 116.290 142.025 ;
        RECT 109.090 134.425 116.290 135.025 ;
        RECT 116.890 142.025 124.090 142.625 ;
        RECT 116.890 135.025 117.490 142.025 ;
        RECT 123.490 135.025 124.090 142.025 ;
        RECT 116.890 134.425 124.090 135.025 ;
        RECT 124.690 142.025 131.890 142.625 ;
        RECT 124.690 135.025 125.290 142.025 ;
        RECT 131.290 135.025 131.890 142.025 ;
        RECT 124.690 134.425 131.890 135.025 ;
        RECT 88.790 133.825 89.790 134.425 ;
        RECT 96.590 133.825 97.590 134.425 ;
        RECT 104.390 133.825 105.390 134.425 ;
        RECT 112.190 133.825 113.190 134.425 ;
        RECT 119.990 133.825 120.990 134.425 ;
        RECT 127.790 133.825 128.790 134.425 ;
        RECT 85.690 133.225 92.890 133.825 ;
        RECT 85.690 126.225 86.290 133.225 ;
        RECT 92.290 126.225 92.890 133.225 ;
        RECT 85.690 125.625 92.890 126.225 ;
        RECT 93.490 133.225 100.690 133.825 ;
        RECT 93.490 126.225 94.090 133.225 ;
        RECT 100.090 126.225 100.690 133.225 ;
        RECT 93.490 125.625 100.690 126.225 ;
        RECT 101.290 133.225 108.490 133.825 ;
        RECT 101.290 126.225 101.890 133.225 ;
        RECT 107.890 126.225 108.490 133.225 ;
        RECT 101.290 125.625 108.490 126.225 ;
        RECT 109.090 133.225 116.290 133.825 ;
        RECT 109.090 126.225 109.690 133.225 ;
        RECT 115.690 126.225 116.290 133.225 ;
        RECT 109.090 125.625 116.290 126.225 ;
        RECT 116.890 133.225 124.090 133.825 ;
        RECT 116.890 126.225 117.490 133.225 ;
        RECT 123.490 126.225 124.090 133.225 ;
        RECT 116.890 125.625 124.090 126.225 ;
        RECT 124.690 133.225 131.890 133.825 ;
        RECT 124.690 126.225 125.290 133.225 ;
        RECT 131.290 126.225 131.890 133.225 ;
        RECT 124.690 125.625 131.890 126.225 ;
        RECT 88.790 125.025 89.790 125.625 ;
        RECT 96.590 125.025 97.590 125.625 ;
        RECT 104.390 125.025 105.390 125.625 ;
        RECT 112.190 125.025 113.190 125.625 ;
        RECT 119.990 125.025 120.990 125.625 ;
        RECT 127.790 125.025 128.790 125.625 ;
        RECT 85.690 124.425 92.890 125.025 ;
        RECT 85.690 117.425 86.290 124.425 ;
        RECT 92.290 117.425 92.890 124.425 ;
        RECT 85.690 116.825 92.890 117.425 ;
        RECT 93.490 124.425 100.690 125.025 ;
        RECT 93.490 117.425 94.090 124.425 ;
        RECT 100.090 117.425 100.690 124.425 ;
        RECT 93.490 116.825 100.690 117.425 ;
        RECT 101.290 124.425 108.490 125.025 ;
        RECT 101.290 117.425 101.890 124.425 ;
        RECT 107.890 117.425 108.490 124.425 ;
        RECT 101.290 116.825 108.490 117.425 ;
        RECT 109.090 124.425 116.290 125.025 ;
        RECT 109.090 117.425 109.690 124.425 ;
        RECT 115.690 117.425 116.290 124.425 ;
        RECT 109.090 116.825 116.290 117.425 ;
        RECT 116.890 124.425 124.090 125.025 ;
        RECT 116.890 117.425 117.490 124.425 ;
        RECT 123.490 117.425 124.090 124.425 ;
        RECT 116.890 116.825 124.090 117.425 ;
        RECT 124.690 124.425 131.890 125.025 ;
        RECT 124.690 117.425 125.290 124.425 ;
        RECT 131.290 117.425 131.890 124.425 ;
        RECT 124.690 116.825 131.890 117.425 ;
        RECT 88.790 116.225 89.790 116.825 ;
        RECT 96.590 116.225 97.590 116.825 ;
        RECT 104.390 116.225 105.390 116.825 ;
        RECT 112.190 116.225 113.190 116.825 ;
        RECT 119.990 116.225 120.990 116.825 ;
        RECT 127.790 116.225 128.790 116.825 ;
        RECT 85.690 115.625 92.890 116.225 ;
        RECT 85.690 109.755 86.290 115.625 ;
        RECT 84.690 108.625 86.290 109.755 ;
        RECT 92.290 108.625 92.890 115.625 ;
        RECT 2.140 107.930 2.760 108.550 ;
        RECT 84.690 108.025 92.890 108.625 ;
        RECT 93.490 115.625 100.690 116.225 ;
        RECT 93.490 108.625 94.090 115.625 ;
        RECT 100.090 108.625 100.690 115.625 ;
        RECT 93.490 108.025 100.690 108.625 ;
        RECT 101.290 115.625 108.490 116.225 ;
        RECT 101.290 108.625 101.890 115.625 ;
        RECT 107.890 108.625 108.490 115.625 ;
        RECT 101.290 108.025 108.490 108.625 ;
        RECT 109.090 115.625 116.290 116.225 ;
        RECT 109.090 108.625 109.690 115.625 ;
        RECT 115.690 108.625 116.290 115.625 ;
        RECT 109.090 108.025 116.290 108.625 ;
        RECT 116.890 115.625 124.090 116.225 ;
        RECT 116.890 108.625 117.490 115.625 ;
        RECT 123.490 108.625 124.090 115.625 ;
        RECT 116.890 108.025 124.090 108.625 ;
        RECT 124.690 115.625 131.890 116.225 ;
        RECT 124.690 108.625 125.290 115.625 ;
        RECT 131.290 108.625 131.890 115.625 ;
        RECT 124.690 108.025 131.890 108.625 ;
        RECT 84.690 108.005 86.170 108.025 ;
        RECT 88.790 107.725 89.790 108.025 ;
        RECT 96.590 107.725 97.590 108.025 ;
        RECT 104.390 107.725 105.390 108.025 ;
        RECT 112.190 107.725 113.190 108.025 ;
        RECT 119.990 107.725 120.990 108.025 ;
        RECT 127.790 107.725 128.790 108.025 ;
        RECT 6.430 101.380 7.890 102.840 ;
        RECT 1.330 47.250 2.790 48.710 ;
        RECT 190.360 1.480 191.820 2.940 ;
      LAYER TopMetal1 ;
        RECT 88.470 159.425 90.110 160.525 ;
        RECT 96.270 159.425 97.910 160.525 ;
        RECT 104.070 159.425 105.710 160.525 ;
        RECT 111.870 159.425 113.510 160.525 ;
        RECT 119.670 159.425 121.310 160.525 ;
        RECT 127.470 159.425 129.110 160.525 ;
        RECT 86.490 157.355 92.090 159.425 ;
        RECT 94.290 157.355 99.890 159.425 ;
        RECT 102.090 157.355 107.690 159.425 ;
        RECT 109.890 157.355 115.490 159.425 ;
        RECT 117.690 157.355 123.290 159.425 ;
        RECT 125.490 157.355 131.090 159.425 ;
        RECT 86.490 155.075 131.090 157.355 ;
        RECT 86.490 152.825 92.090 155.075 ;
        RECT 94.290 152.825 99.890 155.075 ;
        RECT 102.090 152.825 107.690 155.075 ;
        RECT 109.890 152.825 115.490 155.075 ;
        RECT 117.690 152.825 123.290 155.075 ;
        RECT 125.490 152.825 131.090 155.075 ;
        RECT 88.470 150.625 90.110 152.825 ;
        RECT 96.270 150.625 97.910 152.825 ;
        RECT 104.070 150.625 105.710 152.825 ;
        RECT 111.870 150.625 113.510 152.825 ;
        RECT 119.670 150.625 121.310 152.825 ;
        RECT 127.470 150.625 129.110 152.825 ;
        RECT 86.490 148.505 92.090 150.625 ;
        RECT 94.290 148.505 99.890 150.625 ;
        RECT 102.090 148.505 107.690 150.625 ;
        RECT 109.890 148.505 115.490 150.625 ;
        RECT 117.690 148.505 123.290 150.625 ;
        RECT 125.490 148.505 131.090 150.625 ;
        RECT 86.490 146.225 131.090 148.505 ;
        RECT 86.490 144.525 92.090 146.225 ;
        RECT 84.655 144.025 92.090 144.525 ;
        RECT 94.290 144.025 99.890 146.225 ;
        RECT 102.090 144.025 107.690 146.225 ;
        RECT 109.890 144.025 115.490 146.225 ;
        RECT 117.690 144.025 123.290 146.225 ;
        RECT 125.490 144.025 131.090 146.225 ;
        RECT 84.655 143.625 91.960 144.025 ;
        RECT 84.330 141.985 91.960 143.625 ;
        RECT 84.655 141.825 91.960 141.985 ;
        RECT 96.270 141.825 97.910 144.025 ;
        RECT 104.070 141.825 105.710 144.025 ;
        RECT 111.870 141.825 113.510 144.025 ;
        RECT 119.670 141.825 121.310 144.025 ;
        RECT 127.470 141.825 129.110 144.025 ;
        RECT 84.655 140.915 92.090 141.825 ;
        RECT 86.490 139.265 92.090 140.915 ;
        RECT 94.290 139.265 99.890 141.825 ;
        RECT 102.090 139.265 107.690 141.825 ;
        RECT 109.890 139.265 115.490 141.825 ;
        RECT 117.690 139.265 123.290 141.825 ;
        RECT 125.490 139.265 131.090 141.825 ;
        RECT 86.490 136.985 131.300 139.265 ;
        RECT 86.490 135.225 92.090 136.985 ;
        RECT 94.290 135.225 99.890 136.985 ;
        RECT 102.090 135.225 107.690 136.985 ;
        RECT 109.890 135.225 115.490 136.985 ;
        RECT 117.690 135.225 123.290 136.985 ;
        RECT 125.490 135.225 131.090 136.985 ;
        RECT 88.470 133.025 90.110 135.225 ;
        RECT 96.270 133.025 97.910 135.225 ;
        RECT 104.070 133.025 105.710 135.225 ;
        RECT 111.870 133.025 113.510 135.225 ;
        RECT 119.670 133.025 121.310 135.225 ;
        RECT 127.470 133.025 129.110 135.225 ;
        RECT 86.490 131.095 92.090 133.025 ;
        RECT 94.290 131.095 99.890 133.025 ;
        RECT 102.090 131.095 107.690 133.025 ;
        RECT 109.890 131.095 115.490 133.025 ;
        RECT 117.690 131.095 123.290 133.025 ;
        RECT 125.490 131.095 131.090 133.025 ;
        RECT 86.490 128.815 131.090 131.095 ;
        RECT 86.490 126.425 92.090 128.815 ;
        RECT 94.290 126.425 99.890 128.815 ;
        RECT 102.090 126.425 107.690 128.815 ;
        RECT 109.890 126.425 115.490 128.815 ;
        RECT 117.690 126.425 123.290 128.815 ;
        RECT 125.490 126.425 131.090 128.815 ;
        RECT 88.470 124.225 90.110 126.425 ;
        RECT 96.270 124.225 97.910 126.425 ;
        RECT 104.070 124.225 105.710 126.425 ;
        RECT 111.870 124.225 113.510 126.425 ;
        RECT 119.670 124.225 121.310 126.425 ;
        RECT 127.470 124.225 129.110 126.425 ;
        RECT 86.490 122.315 92.090 124.225 ;
        RECT 94.290 122.315 99.890 124.225 ;
        RECT 102.090 122.315 107.690 124.225 ;
        RECT 109.890 122.315 115.490 124.225 ;
        RECT 117.690 122.315 123.290 124.225 ;
        RECT 125.490 122.315 131.090 124.225 ;
        RECT 86.490 120.035 131.090 122.315 ;
        RECT 86.490 117.625 92.090 120.035 ;
        RECT 94.290 117.625 99.890 120.035 ;
        RECT 102.090 117.625 107.690 120.035 ;
        RECT 109.890 117.625 115.490 120.035 ;
        RECT 117.690 117.625 123.290 120.035 ;
        RECT 125.490 117.625 131.090 120.035 ;
        RECT 88.470 115.425 90.110 117.625 ;
        RECT 96.270 115.425 97.910 117.625 ;
        RECT 104.070 115.425 105.710 117.625 ;
        RECT 111.870 115.425 113.510 117.625 ;
        RECT 119.670 115.425 121.310 117.625 ;
        RECT 127.470 115.425 129.110 117.625 ;
        RECT 86.490 113.305 92.090 115.425 ;
        RECT 94.290 113.305 99.890 115.425 ;
        RECT 102.090 113.305 107.690 115.425 ;
        RECT 109.890 113.305 115.490 115.425 ;
        RECT 117.690 113.305 123.290 115.425 ;
        RECT 125.490 113.305 131.090 115.425 ;
        RECT 86.490 111.025 131.090 113.305 ;
        RECT 86.490 108.825 92.090 111.025 ;
        RECT 94.290 108.825 99.890 111.025 ;
        RECT 102.090 108.825 107.690 111.025 ;
        RECT 109.890 108.825 115.490 111.025 ;
        RECT 117.690 108.825 123.290 111.025 ;
        RECT 125.490 108.825 131.090 111.025 ;
        RECT 88.470 107.725 90.110 108.825 ;
        RECT 96.270 107.725 97.910 108.825 ;
        RECT 104.070 107.725 105.710 108.825 ;
        RECT 111.870 107.725 113.510 108.825 ;
        RECT 119.670 107.725 121.310 108.825 ;
        RECT 127.470 107.725 129.110 108.825 ;
        RECT 190.040 2.000 192.140 3.260 ;
        RECT 190.040 1.160 190.165 2.000 ;
        RECT 191.915 1.160 192.140 2.000 ;
  END
END tt_um_ieee_LDO
END LIBRARY

